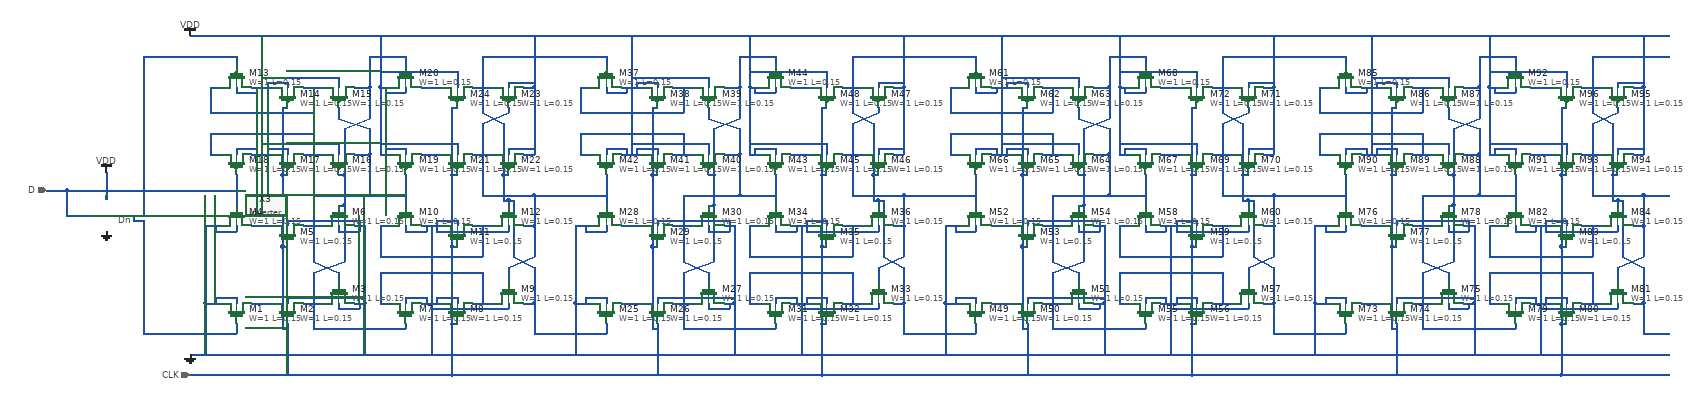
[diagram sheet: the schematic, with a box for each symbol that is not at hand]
v {xschem version=3.4.5 file_version=1.2
}
G {}
K {}
V {}
S {}
E {}
N 525 -420 560 -420 {
lab=Dn}
N 540 -420 540 -410 {
lab=Dn}
N 540 -410 560 -410 {
lab=Dn}
N 410 -420 457.5 -420 {
lab=D}
N 410 -470 410 -420 {
lab=D}
N 370 -470 410 -470 {
lab=D}
N 487.5 -505 487.5 -452.5 {
lab=VDD}
N 740 -500 740 -440 {
lab=D}
N 1070 -500 1070 -440 {
lab=#net1}
N 690 -670 710 -670 {
lab=#net2}
N 690 -540 710 -540 {
lab=#net3}
N 690 -580 690 -540 {
lab=#net3}
N 690 -670 690 -620 {
lab=#net2}
N 680 -400 710 -400 {
lab=GND}
N 680 -400 680 -250 {
lab=GND}
N 680 -250 710 -250 {
lab=GND}
N 1020 -250 1040 -250 {
lab=#net4}
N 1020 -310 1020 -250 {
lab=#net4}
N 1020 -400 1020 -340 {
lab=#net5}
N 1020 -400 1040 -400 {
lab=#net5}
N 970 -250 990 -250 {
lab=GND}
N 990 -400 990 -250 {
lab=GND}
N 970 -400 990 -400 {
lab=GND}
N 1020 -670 1040 -670 {
lab=VDD}
N 1020 -670 1020 -540 {
lab=VDD}
N 1020 -540 1040 -540 {
lab=VDD}
N 1300 -540 1320 -540 {
lab=VDD}
N 1320 -670 1320 -540 {
lab=VDD}
N 1300 -670 1320 -670 {
lab=VDD}
N 970 -670 1000 -670 {
lab=#net6}
N 1000 -730 1000 -670 {
lab=#net6}
N 1000 -730 1070 -730 {
lab=#net6}
N 1070 -730 1070 -710 {
lab=#net6}
N 1000 -670 1000 -610 {
lab=#net6}
N 840 -210 840 -190 {
lab=CLK}
N 970 -540 990 -540 {
lab=#net1}
N 1000 -540 1000 -460 {
lab=#net1}
N 990 -540 1000 -540 {
lab=#net1}
N 1000 -590 1000 -540 {
lab=#net1}
N 940 -610 1000 -590 {
lab=#net1}
N 940 -630 940 -610 {
lab=#net1}
N 1300 -250 1320 -250 {
lab=#net7}
N 1320 -320 1320 -250 {
lab=#net7}
N 1270 -320 1270 -290 {
lab=#net8}
N 1270 -320 1320 -340 {
lab=#net8}
N 1320 -400 1320 -340 {
lab=#net8}
N 1300 -400 1320 -400 {
lab=#net8}
N 1320 -460 1320 -400 {
lab=#net8}
N 1320 -460 1370 -460 {
lab=#net8}
N 740 -730 740 -710 {
lab=Dn}
N 650 -730 740 -730 {
lab=Dn}
N 740 -210 740 -190 {
lab=Dn}
N 650 -190 740 -190 {
lab=Dn}
N 650 -150 1330 -150 {
lab=GND}
N 990 -250 990 -150 {
lab=GND}
N 840 -190 840 -110 {
lab=CLK}
N 650 -770 1330 -770 {
lab=VDD}
N 1020 -770 1020 -670 {
lab=VDD}
N 1320 -770 1320 -670 {
lab=VDD}
N 770 -670 810 -670 {
lab=VDD}
N 770 -540 810 -540 {
lab=VDD}
N 870 -670 910 -670 {
lab=#net2}
N 890 -670 890 -620 {
lab=#net2}
N 690 -620 890 -620 {
lab=#net2}
N 870 -540 910 -540 {
lab=#net3}
N 690 -580 890 -580 {
lab=#net3}
N 890 -580 890 -540 {
lab=#net3}
N 770 -400 810 -400 {
lab=#net9}
N 770 -250 810 -250 {
lab=#net10}
N 870 -250 910 -250 {
lab=#net6}
N 740 -400 740 -390 {
lab=GND}
N 700 -390 740 -390 {
lab=GND}
N 700 -400 700 -390 {
lab=GND}
N 1100 -250 1140 -250 {
lab=GND}
N 1100 -400 1140 -400 {
lab=GND}
N 1200 -250 1240 -250 {
lab=#net4}
N 1200 -400 1240 -400 {
lab=#net5}
N 1020 -340 1220 -340 {
lab=#net5}
N 1220 -400 1220 -340 {
lab=#net5}
N 1070 -260 1070 -250 {
lab=GND}
N 1070 -260 1110 -260 {
lab=GND}
N 1110 -260 1110 -250 {
lab=GND}
N 1020 -310 1220 -310 {
lab=#net4}
N 1220 -310 1220 -250 {
lab=#net4}
N 1100 -540 1140 -540 {
lab=#net11}
N 1200 -540 1240 -540 {
lab=#net8}
N 830 -200 840 -200 {
lab=CLK}
N 830 -360 830 -200 {
lab=CLK}
N 830 -360 840 -360 {
lab=CLK}
N 830 -500 830 -360 {
lab=CLK}
N 830 -500 840 -500 {
lab=CLK}
N 790 -670 790 -540 {
lab=VDD}
N 790 -770 790 -670 {
lab=VDD}
N 940 -500 950 -500 {
lab=#net6}
N 950 -590 950 -500 {
lab=#net6}
N 950 -590 1000 -610 {
lab=#net6}
N 1000 -460 1070 -460 {
lab=#net1}
N 1120 -250 1120 -150 {
lab=GND}
N 1120 -400 1120 -250 {
lab=GND}
N 1160 -210 1170 -210 {
lab=CLK}
N 1160 -360 1170 -360 {
lab=CLK}
N 1160 -500 1170 -500 {
lab=CLK}
N 1200 -670 1240 -670 {
lab=#net7}
N 1160 -630 1160 -500 {
lab=CLK}
N 1160 -630 1170 -630 {
lab=CLK}
N 1100 -670 1140 -670 {
lab=#net12}
N 1220 -730 1370 -730 {
lab=#net7}
N 1220 -730 1220 -670 {
lab=#net7}
N 1260 -500 1270 -500 {
lab=#net7}
N 1260 -600 1260 -500 {
lab=#net7}
N 1220 -620 1260 -600 {
lab=#net7}
N 1220 -670 1220 -620 {
lab=#net7}
N 1270 -630 1270 -620 {
lab=#net8}
N 1220 -600 1270 -620 {
lab=#net8}
N 1220 -600 1220 -540 {
lab=#net8}
N 1220 -540 1220 -460 {
lab=#net8}
N 1220 -460 1320 -460 {
lab=#net8}
N 1270 -450 1270 -440 {
lab=#net7}
N 1270 -450 1280 -450 {
lab=#net7}
N 1280 -450 1280 -340 {
lab=#net7}
N 1280 -340 1320 -320 {
lab=#net7}
N 1260 -450 1270 -450 {
lab=#net7}
N 1260 -500 1260 -450 {
lab=#net7}
N 1320 -250 1320 -190 {
lab=#net7}
N 1320 -190 1330 -190 {
lab=#net7}
N 1160 -210 1160 -110 {
lab=CLK}
N 890 -250 890 -200 {
lab=#net6}
N 890 -200 1070 -200 {
lab=#net6}
N 1070 -210 1070 -200 {
lab=#net6}
N 870 -400 910 -400 {
lab=#net1}
N 890 -460 890 -400 {
lab=#net1}
N 890 -460 1000 -460 {
lab=#net1}
N 940 -440 950 -440 {
lab=#net6}
N 950 -500 950 -440 {
lab=#net6}
N 940 -310 940 -290 {
lab=#net1}
N 890 -330 940 -310 {
lab=#net1}
N 890 -400 890 -330 {
lab=#net1}
N 950 -440 950 -330 {
lab=#net6}
N 890 -310 950 -330 {
lab=#net6}
N 890 -310 890 -250 {
lab=#net6}
N 740 -260 740 -250 {
lab=GND}
N 700 -260 740 -260 {
lab=GND}
N 700 -260 700 -250 {
lab=GND}
N 940 -250 940 -240 {
lab=GND}
N 940 -240 980 -240 {
lab=GND}
N 980 -250 980 -240 {
lab=GND}
N 940 -400 940 -390 {
lab=GND}
N 940 -390 980 -390 {
lab=GND}
N 980 -400 980 -390 {
lab=GND}
N 1070 -400 1070 -390 {
lab=GND}
N 1070 -390 1110 -390 {
lab=GND}
N 1110 -400 1110 -390 {
lab=GND}
N 1170 -410 1170 -400 {
lab=GND}
N 1130 -410 1170 -410 {
lab=GND}
N 1130 -410 1130 -400 {
lab=GND}
N 1170 -260 1170 -250 {
lab=GND}
N 1130 -260 1170 -260 {
lab=GND}
N 1130 -260 1130 -250 {
lab=GND}
N 1160 -500 1160 -360 {
lab=CLK}
N 1160 -360 1160 -210 {
lab=CLK}
N 840 -410 840 -400 {
lab=GND}
N 840 -410 980 -410 {
lab=GND}
N 980 -410 980 -400 {
lab=GND}
N 840 -260 840 -250 {
lab=GND}
N 840 -260 990 -260 {
lab=GND}
N 1270 -400 1270 -390 {
lab=GND}
N 1130 -390 1270 -390 {
lab=GND}
N 1130 -400 1130 -390 {
lab=GND}
N 1270 -250 1270 -240 {
lab=GND}
N 1120 -240 1270 -240 {
lab=GND}
N 840 -680 840 -670 {
lab=VDD}
N 800 -680 840 -680 {
lab=VDD}
N 800 -680 800 -670 {
lab=VDD}
N 740 -670 740 -660 {
lab=VDD}
N 740 -660 780 -660 {
lab=VDD}
N 780 -670 780 -660 {
lab=VDD}
N 740 -550 740 -540 {
lab=VDD}
N 740 -550 780 -550 {
lab=VDD}
N 780 -550 780 -540 {
lab=VDD}
N 840 -550 840 -540 {
lab=VDD}
N 800 -550 840 -550 {
lab=VDD}
N 800 -550 800 -540 {
lab=VDD}
N 940 -690 940 -670 {
lab=VDD}
N 790 -690 940 -690 {
lab=VDD}
N 940 -560 940 -540 {
lab=VDD}
N 790 -560 940 -560 {
lab=VDD}
N 1070 -670 1070 -660 {
lab=VDD}
N 1030 -660 1070 -660 {
lab=VDD}
N 1030 -670 1030 -660 {
lab=VDD}
N 1070 -550 1070 -540 {
lab=VDD}
N 1030 -550 1070 -550 {
lab=VDD}
N 1030 -550 1030 -540 {
lab=VDD}
N 1170 -700 1170 -670 {
lab=VDD}
N 1020 -700 1170 -700 {
lab=VDD}
N 1170 -560 1170 -540 {
lab=VDD}
N 1020 -560 1170 -560 {
lab=VDD}
N 1270 -680 1270 -670 {
lab=VDD}
N 1270 -680 1320 -680 {
lab=VDD}
N 1270 -550 1270 -540 {
lab=VDD}
N 1270 -550 1320 -550 {
lab=VDD}
N 830 -630 830 -500 {
lab=CLK}
N 830 -630 840 -630 {
lab=CLK}
N 680 -250 680 -150 {
lab=GND}
N 410 -470 740 -470 {
lab=D}
N 560 -730 560 -420 {
lab=Dn}
N 560 -730 650 -730 {
lab=Dn}
N 560 -410 560 -190 {
lab=Dn}
N 560 -190 650 -190 {
lab=Dn}
N 650 -110 1160 -110 {
lab=CLK}
N 1460 -500 1460 -440 {
lab=#net13}
N 1790 -500 1790 -440 {
lab=#net14}
N 1410 -670 1430 -670 {
lab=#net15}
N 1410 -540 1430 -540 {
lab=#net16}
N 1410 -580 1410 -540 {
lab=#net16}
N 1410 -670 1410 -620 {
lab=#net15}
N 1400 -400 1430 -400 {
lab=#net17}
N 1400 -400 1400 -250 {
lab=#net17}
N 1400 -250 1430 -250 {
lab=#net17}
N 1740 -250 1760 -250 {
lab=#net18}
N 1740 -310 1740 -250 {
lab=#net18}
N 1740 -400 1740 -340 {
lab=#net19}
N 1740 -400 1760 -400 {
lab=#net19}
N 1690 -250 1710 -250 {
lab=#net17}
N 1710 -400 1710 -250 {
lab=#net17}
N 1690 -400 1710 -400 {
lab=#net17}
N 1740 -670 1760 -670 {
lab=#net20}
N 1740 -670 1740 -540 {
lab=#net20}
N 1740 -540 1760 -540 {
lab=#net20}
N 2020 -540 2040 -540 {
lab=#net20}
N 2040 -670 2040 -540 {
lab=#net20}
N 2020 -670 2040 -670 {
lab=#net20}
N 1690 -670 1720 -670 {
lab=#net21}
N 1720 -730 1720 -670 {
lab=#net21}
N 1720 -730 1790 -730 {
lab=#net21}
N 1790 -730 1790 -710 {
lab=#net21}
N 1720 -670 1720 -610 {
lab=#net21}
N 1560 -210 1560 -190 {
lab=#net22}
N 1690 -540 1710 -540 {
lab=#net14}
N 1720 -540 1720 -460 {
lab=#net14}
N 1710 -540 1720 -540 {
lab=#net14}
N 1720 -590 1720 -540 {
lab=#net14}
N 1660 -610 1720 -590 {
lab=#net14}
N 1660 -630 1660 -610 {
lab=#net14}
N 2020 -250 2040 -250 {
lab=#net23}
N 2040 -320 2040 -250 {
lab=#net23}
N 1990 -320 1990 -290 {
lab=#net24}
N 1990 -320 2040 -340 {
lab=#net24}
N 2040 -400 2040 -340 {
lab=#net24}
N 2020 -400 2040 -400 {
lab=#net24}
N 2040 -460 2040 -400 {
lab=#net24}
N 2040 -460 2090 -460 {
lab=#net24}
N 1460 -730 1460 -710 {
lab=#net25}
N 1460 -210 1460 -190 {
lab=#net26}
N 1370 -150 2050 -150 {
lab=#net17}
N 1710 -250 1710 -150 {
lab=#net17}
N 1560 -190 1560 -110 {
lab=#net22}
N 1370 -770 2050 -770 {
lab=#net20}
N 1740 -770 1740 -670 {
lab=#net20}
N 2040 -770 2040 -670 {
lab=#net20}
N 1490 -670 1530 -670 {
lab=#net20}
N 1490 -540 1530 -540 {
lab=#net20}
N 1590 -670 1630 -670 {
lab=#net15}
N 1610 -670 1610 -620 {
lab=#net15}
N 1410 -620 1610 -620 {
lab=#net15}
N 1590 -540 1630 -540 {
lab=#net16}
N 1410 -580 1610 -580 {
lab=#net16}
N 1610 -580 1610 -540 {
lab=#net16}
N 1490 -400 1530 -400 {
lab=#net27}
N 1490 -250 1530 -250 {
lab=#net28}
N 1590 -250 1630 -250 {
lab=#net21}
N 1460 -400 1460 -390 {
lab=#net17}
N 1420 -390 1460 -390 {
lab=#net17}
N 1420 -400 1420 -390 {
lab=#net17}
N 1820 -250 1860 -250 {
lab=#net17}
N 1820 -400 1860 -400 {
lab=#net17}
N 1920 -250 1960 -250 {
lab=#net18}
N 1920 -400 1960 -400 {
lab=#net19}
N 1740 -340 1940 -340 {
lab=#net19}
N 1940 -400 1940 -340 {
lab=#net19}
N 1790 -260 1790 -250 {
lab=#net17}
N 1790 -260 1830 -260 {
lab=#net17}
N 1830 -260 1830 -250 {
lab=#net17}
N 1740 -310 1940 -310 {
lab=#net18}
N 1940 -310 1940 -250 {
lab=#net18}
N 1820 -540 1860 -540 {
lab=#net29}
N 1920 -540 1960 -540 {
lab=#net24}
N 1550 -200 1560 -200 {
lab=#net22}
N 1550 -360 1550 -200 {
lab=#net22}
N 1550 -360 1560 -360 {
lab=#net22}
N 1550 -500 1550 -360 {
lab=#net22}
N 1550 -500 1560 -500 {
lab=#net22}
N 1510 -670 1510 -540 {
lab=#net20}
N 1510 -770 1510 -670 {
lab=#net20}
N 1660 -500 1670 -500 {
lab=#net21}
N 1670 -590 1670 -500 {
lab=#net21}
N 1670 -590 1720 -610 {
lab=#net21}
N 1720 -460 1790 -460 {
lab=#net14}
N 1840 -250 1840 -150 {
lab=#net17}
N 1840 -400 1840 -250 {
lab=#net17}
N 1880 -210 1890 -210 {
lab=#net22}
N 1880 -360 1890 -360 {
lab=#net22}
N 1880 -500 1890 -500 {
lab=#net22}
N 1920 -670 1960 -670 {
lab=#net23}
N 1880 -630 1880 -500 {
lab=#net22}
N 1880 -630 1890 -630 {
lab=#net22}
N 1820 -670 1860 -670 {
lab=#net30}
N 1940 -730 2090 -730 {
lab=#net23}
N 1940 -730 1940 -670 {
lab=#net23}
N 1980 -500 1990 -500 {
lab=#net23}
N 1980 -600 1980 -500 {
lab=#net23}
N 1940 -620 1980 -600 {
lab=#net23}
N 1940 -670 1940 -620 {
lab=#net23}
N 1990 -630 1990 -620 {
lab=#net24}
N 1940 -600 1990 -620 {
lab=#net24}
N 1940 -600 1940 -540 {
lab=#net24}
N 1940 -540 1940 -460 {
lab=#net24}
N 1940 -460 2040 -460 {
lab=#net24}
N 1990 -450 1990 -440 {
lab=#net23}
N 1990 -450 2000 -450 {
lab=#net23}
N 2000 -450 2000 -340 {
lab=#net23}
N 2000 -340 2040 -320 {
lab=#net23}
N 1980 -450 1990 -450 {
lab=#net23}
N 1980 -500 1980 -450 {
lab=#net23}
N 2040 -250 2040 -190 {
lab=#net23}
N 2040 -190 2050 -190 {
lab=#net23}
N 1880 -210 1880 -110 {
lab=#net22}
N 1610 -250 1610 -200 {
lab=#net21}
N 1610 -200 1790 -200 {
lab=#net21}
N 1790 -210 1790 -200 {
lab=#net21}
N 1590 -400 1630 -400 {
lab=#net14}
N 1610 -460 1610 -400 {
lab=#net14}
N 1610 -460 1720 -460 {
lab=#net14}
N 1660 -440 1670 -440 {
lab=#net21}
N 1670 -500 1670 -440 {
lab=#net21}
N 1660 -310 1660 -290 {
lab=#net14}
N 1610 -330 1660 -310 {
lab=#net14}
N 1610 -400 1610 -330 {
lab=#net14}
N 1670 -440 1670 -330 {
lab=#net21}
N 1610 -310 1670 -330 {
lab=#net21}
N 1610 -310 1610 -250 {
lab=#net21}
N 1460 -260 1460 -250 {
lab=#net17}
N 1420 -260 1460 -260 {
lab=#net17}
N 1420 -260 1420 -250 {
lab=#net17}
N 1660 -250 1660 -240 {
lab=#net17}
N 1660 -240 1700 -240 {
lab=#net17}
N 1700 -250 1700 -240 {
lab=#net17}
N 1660 -400 1660 -390 {
lab=#net17}
N 1660 -390 1700 -390 {
lab=#net17}
N 1700 -400 1700 -390 {
lab=#net17}
N 1790 -400 1790 -390 {
lab=#net17}
N 1790 -390 1830 -390 {
lab=#net17}
N 1830 -400 1830 -390 {
lab=#net17}
N 1890 -410 1890 -400 {
lab=#net17}
N 1850 -410 1890 -410 {
lab=#net17}
N 1850 -410 1850 -400 {
lab=#net17}
N 1890 -260 1890 -250 {
lab=#net17}
N 1850 -260 1890 -260 {
lab=#net17}
N 1850 -260 1850 -250 {
lab=#net17}
N 1880 -500 1880 -360 {
lab=#net22}
N 1880 -360 1880 -210 {
lab=#net22}
N 1560 -410 1560 -400 {
lab=#net17}
N 1560 -410 1700 -410 {
lab=#net17}
N 1700 -410 1700 -400 {
lab=#net17}
N 1560 -260 1560 -250 {
lab=#net17}
N 1560 -260 1710 -260 {
lab=#net17}
N 1990 -400 1990 -390 {
lab=#net17}
N 1850 -390 1990 -390 {
lab=#net17}
N 1850 -400 1850 -390 {
lab=#net17}
N 1990 -250 1990 -240 {
lab=#net17}
N 1840 -240 1990 -240 {
lab=#net17}
N 1560 -680 1560 -670 {
lab=#net20}
N 1520 -680 1560 -680 {
lab=#net20}
N 1520 -680 1520 -670 {
lab=#net20}
N 1460 -670 1460 -660 {
lab=#net20}
N 1460 -660 1500 -660 {
lab=#net20}
N 1500 -670 1500 -660 {
lab=#net20}
N 1460 -550 1460 -540 {
lab=#net20}
N 1460 -550 1500 -550 {
lab=#net20}
N 1500 -550 1500 -540 {
lab=#net20}
N 1560 -550 1560 -540 {
lab=#net20}
N 1520 -550 1560 -550 {
lab=#net20}
N 1520 -550 1520 -540 {
lab=#net20}
N 1660 -690 1660 -670 {
lab=#net20}
N 1510 -690 1660 -690 {
lab=#net20}
N 1660 -560 1660 -540 {
lab=#net20}
N 1510 -560 1660 -560 {
lab=#net20}
N 1790 -670 1790 -660 {
lab=#net20}
N 1750 -660 1790 -660 {
lab=#net20}
N 1750 -670 1750 -660 {
lab=#net20}
N 1790 -550 1790 -540 {
lab=#net20}
N 1750 -550 1790 -550 {
lab=#net20}
N 1750 -550 1750 -540 {
lab=#net20}
N 1890 -700 1890 -670 {
lab=#net20}
N 1740 -700 1890 -700 {
lab=#net20}
N 1890 -560 1890 -540 {
lab=#net20}
N 1740 -560 1890 -560 {
lab=#net20}
N 1990 -680 1990 -670 {
lab=#net20}
N 1990 -680 2040 -680 {
lab=#net20}
N 1990 -550 1990 -540 {
lab=#net20}
N 1990 -550 2040 -550 {
lab=#net20}
N 1550 -630 1550 -500 {
lab=#net22}
N 1550 -630 1560 -630 {
lab=#net22}
N 1400 -250 1400 -150 {
lab=#net17}
N 1370 -110 1880 -110 {
lab=#net22}
N 1160 -110 1330 -110 {
lab=CLK}
N 1370 -190 1460 -190 {
lab=#net26}
N 1370 -730 1460 -730 {
lab=#net25}
N 1370 -460 1460 -460 {
lab=#net13}
N 1330 -770 1370 -770 {
lab=VDD}
N 1330 -190 1370 -190 {
lab=#net7}
N 1330 -150 1370 -150 {
lab=GND}
N 1330 -110 1370 -110 {
lab=CLK}
N 2050 -770 2090 -770 {
lab=#net20}
N 2050 -190 2090 -190 {
lab=#net23}
N 2050 -150 2090 -150 {
lab=#net17}
N 1880 -110 2090 -110 {
lab=#net22}
N 2180 -500 2180 -440 {
lab=#net13}
N 2510 -500 2510 -440 {
lab=#net14}
N 2130 -670 2150 -670 {
lab=#net15}
N 2130 -540 2150 -540 {
lab=#net16}
N 2130 -580 2130 -540 {
lab=#net16}
N 2130 -670 2130 -620 {
lab=#net15}
N 2120 -400 2150 -400 {
lab=#net17}
N 2120 -400 2120 -250 {
lab=#net17}
N 2120 -250 2150 -250 {
lab=#net17}
N 2460 -250 2480 -250 {
lab=#net18}
N 2460 -310 2460 -250 {
lab=#net18}
N 2460 -400 2460 -340 {
lab=#net19}
N 2460 -400 2480 -400 {
lab=#net19}
N 2410 -250 2430 -250 {
lab=#net17}
N 2430 -400 2430 -250 {
lab=#net17}
N 2410 -400 2430 -400 {
lab=#net17}
N 2460 -670 2480 -670 {
lab=#net20}
N 2460 -670 2460 -540 {
lab=#net20}
N 2460 -540 2480 -540 {
lab=#net20}
N 2740 -540 2760 -540 {
lab=#net20}
N 2760 -670 2760 -540 {
lab=#net20}
N 2740 -670 2760 -670 {
lab=#net20}
N 2410 -670 2440 -670 {
lab=#net21}
N 2440 -730 2440 -670 {
lab=#net21}
N 2440 -730 2510 -730 {
lab=#net21}
N 2510 -730 2510 -710 {
lab=#net21}
N 2440 -670 2440 -610 {
lab=#net21}
N 2280 -210 2280 -190 {
lab=#net22}
N 2410 -540 2430 -540 {
lab=#net14}
N 2440 -540 2440 -460 {
lab=#net14}
N 2430 -540 2440 -540 {
lab=#net14}
N 2440 -590 2440 -540 {
lab=#net14}
N 2380 -610 2440 -590 {
lab=#net14}
N 2380 -630 2380 -610 {
lab=#net14}
N 2740 -250 2760 -250 {
lab=#net23}
N 2760 -320 2760 -250 {
lab=#net23}
N 2710 -320 2710 -290 {
lab=#net24}
N 2710 -320 2760 -340 {
lab=#net24}
N 2760 -400 2760 -340 {
lab=#net24}
N 2740 -400 2760 -400 {
lab=#net24}
N 2760 -460 2760 -400 {
lab=#net24}
N 2760 -460 2810 -460 {
lab=#net24}
N 2180 -730 2180 -710 {
lab=#net25}
N 2180 -210 2180 -190 {
lab=#net26}
N 2090 -150 2770 -150 {
lab=#net17}
N 2430 -250 2430 -150 {
lab=#net17}
N 2280 -190 2280 -110 {
lab=#net22}
N 2090 -770 2770 -770 {
lab=#net20}
N 2460 -770 2460 -670 {
lab=#net20}
N 2760 -770 2760 -670 {
lab=#net20}
N 2210 -670 2250 -670 {
lab=#net20}
N 2210 -540 2250 -540 {
lab=#net20}
N 2310 -670 2350 -670 {
lab=#net15}
N 2330 -670 2330 -620 {
lab=#net15}
N 2130 -620 2330 -620 {
lab=#net15}
N 2310 -540 2350 -540 {
lab=#net16}
N 2130 -580 2330 -580 {
lab=#net16}
N 2330 -580 2330 -540 {
lab=#net16}
N 2210 -400 2250 -400 {
lab=#net27}
N 2210 -250 2250 -250 {
lab=#net28}
N 2310 -250 2350 -250 {
lab=#net21}
N 2180 -400 2180 -390 {
lab=#net17}
N 2140 -390 2180 -390 {
lab=#net17}
N 2140 -400 2140 -390 {
lab=#net17}
N 2540 -250 2580 -250 {
lab=#net17}
N 2540 -400 2580 -400 {
lab=#net17}
N 2640 -250 2680 -250 {
lab=#net18}
N 2640 -400 2680 -400 {
lab=#net19}
N 2460 -340 2660 -340 {
lab=#net19}
N 2660 -400 2660 -340 {
lab=#net19}
N 2510 -260 2510 -250 {
lab=#net17}
N 2510 -260 2550 -260 {
lab=#net17}
N 2550 -260 2550 -250 {
lab=#net17}
N 2460 -310 2660 -310 {
lab=#net18}
N 2660 -310 2660 -250 {
lab=#net18}
N 2540 -540 2580 -540 {
lab=#net29}
N 2640 -540 2680 -540 {
lab=#net24}
N 2270 -200 2280 -200 {
lab=#net22}
N 2270 -360 2270 -200 {
lab=#net22}
N 2270 -360 2280 -360 {
lab=#net22}
N 2270 -500 2270 -360 {
lab=#net22}
N 2270 -500 2280 -500 {
lab=#net22}
N 2230 -670 2230 -540 {
lab=#net20}
N 2230 -770 2230 -670 {
lab=#net20}
N 2380 -500 2390 -500 {
lab=#net21}
N 2390 -590 2390 -500 {
lab=#net21}
N 2390 -590 2440 -610 {
lab=#net21}
N 2440 -460 2510 -460 {
lab=#net14}
N 2560 -250 2560 -150 {
lab=#net17}
N 2560 -400 2560 -250 {
lab=#net17}
N 2600 -210 2610 -210 {
lab=#net22}
N 2600 -360 2610 -360 {
lab=#net22}
N 2600 -500 2610 -500 {
lab=#net22}
N 2640 -670 2680 -670 {
lab=#net23}
N 2600 -630 2600 -500 {
lab=#net22}
N 2600 -630 2610 -630 {
lab=#net22}
N 2540 -670 2580 -670 {
lab=#net30}
N 2660 -730 2810 -730 {
lab=#net23}
N 2660 -730 2660 -670 {
lab=#net23}
N 2700 -500 2710 -500 {
lab=#net23}
N 2700 -600 2700 -500 {
lab=#net23}
N 2660 -620 2700 -600 {
lab=#net23}
N 2660 -670 2660 -620 {
lab=#net23}
N 2710 -630 2710 -620 {
lab=#net24}
N 2660 -600 2710 -620 {
lab=#net24}
N 2660 -600 2660 -540 {
lab=#net24}
N 2660 -540 2660 -460 {
lab=#net24}
N 2660 -460 2760 -460 {
lab=#net24}
N 2710 -450 2710 -440 {
lab=#net23}
N 2710 -450 2720 -450 {
lab=#net23}
N 2720 -450 2720 -340 {
lab=#net23}
N 2720 -340 2760 -320 {
lab=#net23}
N 2700 -450 2710 -450 {
lab=#net23}
N 2700 -500 2700 -450 {
lab=#net23}
N 2760 -250 2760 -190 {
lab=#net23}
N 2760 -190 2770 -190 {
lab=#net23}
N 2600 -210 2600 -110 {
lab=#net22}
N 2330 -250 2330 -200 {
lab=#net21}
N 2330 -200 2510 -200 {
lab=#net21}
N 2510 -210 2510 -200 {
lab=#net21}
N 2310 -400 2350 -400 {
lab=#net14}
N 2330 -460 2330 -400 {
lab=#net14}
N 2330 -460 2440 -460 {
lab=#net14}
N 2380 -440 2390 -440 {
lab=#net21}
N 2390 -500 2390 -440 {
lab=#net21}
N 2380 -310 2380 -290 {
lab=#net14}
N 2330 -330 2380 -310 {
lab=#net14}
N 2330 -400 2330 -330 {
lab=#net14}
N 2390 -440 2390 -330 {
lab=#net21}
N 2330 -310 2390 -330 {
lab=#net21}
N 2330 -310 2330 -250 {
lab=#net21}
N 2180 -260 2180 -250 {
lab=#net17}
N 2140 -260 2180 -260 {
lab=#net17}
N 2140 -260 2140 -250 {
lab=#net17}
N 2380 -250 2380 -240 {
lab=#net17}
N 2380 -240 2420 -240 {
lab=#net17}
N 2420 -250 2420 -240 {
lab=#net17}
N 2380 -400 2380 -390 {
lab=#net17}
N 2380 -390 2420 -390 {
lab=#net17}
N 2420 -400 2420 -390 {
lab=#net17}
N 2510 -400 2510 -390 {
lab=#net17}
N 2510 -390 2550 -390 {
lab=#net17}
N 2550 -400 2550 -390 {
lab=#net17}
N 2610 -410 2610 -400 {
lab=#net17}
N 2570 -410 2610 -410 {
lab=#net17}
N 2570 -410 2570 -400 {
lab=#net17}
N 2610 -260 2610 -250 {
lab=#net17}
N 2570 -260 2610 -260 {
lab=#net17}
N 2570 -260 2570 -250 {
lab=#net17}
N 2600 -500 2600 -360 {
lab=#net22}
N 2600 -360 2600 -210 {
lab=#net22}
N 2280 -410 2280 -400 {
lab=#net17}
N 2280 -410 2420 -410 {
lab=#net17}
N 2420 -410 2420 -400 {
lab=#net17}
N 2280 -260 2280 -250 {
lab=#net17}
N 2280 -260 2430 -260 {
lab=#net17}
N 2710 -400 2710 -390 {
lab=#net17}
N 2570 -390 2710 -390 {
lab=#net17}
N 2570 -400 2570 -390 {
lab=#net17}
N 2710 -250 2710 -240 {
lab=#net17}
N 2560 -240 2710 -240 {
lab=#net17}
N 2280 -680 2280 -670 {
lab=#net20}
N 2240 -680 2280 -680 {
lab=#net20}
N 2240 -680 2240 -670 {
lab=#net20}
N 2180 -670 2180 -660 {
lab=#net20}
N 2180 -660 2220 -660 {
lab=#net20}
N 2220 -670 2220 -660 {
lab=#net20}
N 2180 -550 2180 -540 {
lab=#net20}
N 2180 -550 2220 -550 {
lab=#net20}
N 2220 -550 2220 -540 {
lab=#net20}
N 2280 -550 2280 -540 {
lab=#net20}
N 2240 -550 2280 -550 {
lab=#net20}
N 2240 -550 2240 -540 {
lab=#net20}
N 2380 -690 2380 -670 {
lab=#net20}
N 2230 -690 2380 -690 {
lab=#net20}
N 2380 -560 2380 -540 {
lab=#net20}
N 2230 -560 2380 -560 {
lab=#net20}
N 2510 -670 2510 -660 {
lab=#net20}
N 2470 -660 2510 -660 {
lab=#net20}
N 2470 -670 2470 -660 {
lab=#net20}
N 2510 -550 2510 -540 {
lab=#net20}
N 2470 -550 2510 -550 {
lab=#net20}
N 2470 -550 2470 -540 {
lab=#net20}
N 2610 -700 2610 -670 {
lab=#net20}
N 2460 -700 2610 -700 {
lab=#net20}
N 2610 -560 2610 -540 {
lab=#net20}
N 2460 -560 2610 -560 {
lab=#net20}
N 2710 -680 2710 -670 {
lab=#net20}
N 2710 -680 2760 -680 {
lab=#net20}
N 2710 -550 2710 -540 {
lab=#net20}
N 2710 -550 2760 -550 {
lab=#net20}
N 2270 -630 2270 -500 {
lab=#net22}
N 2270 -630 2280 -630 {
lab=#net22}
N 2120 -250 2120 -150 {
lab=#net17}
N 2090 -110 2600 -110 {
lab=#net22}
N 2090 -190 2180 -190 {
lab=#net26}
N 2090 -730 2180 -730 {
lab=#net25}
N 2090 -460 2180 -460 {
lab=#net13}
N 2770 -770 2810 -770 {
lab=#net20}
N 2770 -190 2810 -190 {
lab=#net23}
N 2770 -150 2810 -150 {
lab=#net17}
N 2600 -110 2810 -110 {
lab=#net22}
N 2900 -500 2900 -440 {
lab=#net13}
N 3230 -500 3230 -440 {
lab=#net14}
N 2850 -670 2870 -670 {
lab=#net15}
N 2850 -540 2870 -540 {
lab=#net16}
N 2850 -580 2850 -540 {
lab=#net16}
N 2850 -670 2850 -620 {
lab=#net15}
N 2840 -400 2870 -400 {
lab=#net17}
N 2840 -400 2840 -250 {
lab=#net17}
N 2840 -250 2870 -250 {
lab=#net17}
N 3180 -250 3200 -250 {
lab=#net18}
N 3180 -310 3180 -250 {
lab=#net18}
N 3180 -400 3180 -340 {
lab=#net19}
N 3180 -400 3200 -400 {
lab=#net19}
N 3130 -250 3150 -250 {
lab=#net17}
N 3150 -400 3150 -250 {
lab=#net17}
N 3130 -400 3150 -400 {
lab=#net17}
N 3180 -670 3200 -670 {
lab=#net20}
N 3180 -670 3180 -540 {
lab=#net20}
N 3180 -540 3200 -540 {
lab=#net20}
N 3460 -540 3480 -540 {
lab=#net20}
N 3480 -670 3480 -540 {
lab=#net20}
N 3460 -670 3480 -670 {
lab=#net20}
N 3130 -670 3160 -670 {
lab=#net21}
N 3160 -730 3160 -670 {
lab=#net21}
N 3160 -730 3230 -730 {
lab=#net21}
N 3230 -730 3230 -710 {
lab=#net21}
N 3160 -670 3160 -610 {
lab=#net21}
N 3000 -210 3000 -190 {
lab=#net22}
N 3130 -540 3150 -540 {
lab=#net14}
N 3160 -540 3160 -460 {
lab=#net14}
N 3150 -540 3160 -540 {
lab=#net14}
N 3160 -590 3160 -540 {
lab=#net14}
N 3100 -610 3160 -590 {
lab=#net14}
N 3100 -630 3100 -610 {
lab=#net14}
N 3460 -250 3480 -250 {
lab=#net23}
N 3480 -320 3480 -250 {
lab=#net23}
N 3430 -320 3430 -290 {
lab=#net24}
N 3430 -320 3480 -340 {
lab=#net24}
N 3480 -400 3480 -340 {
lab=#net24}
N 3460 -400 3480 -400 {
lab=#net24}
N 3480 -460 3480 -400 {
lab=#net24}
N 3480 -460 3530 -460 {
lab=#net24}
N 2900 -730 2900 -710 {
lab=#net25}
N 2900 -210 2900 -190 {
lab=#net26}
N 2810 -150 3490 -150 {
lab=#net17}
N 3150 -250 3150 -150 {
lab=#net17}
N 3000 -190 3000 -110 {
lab=#net22}
N 2810 -770 3490 -770 {
lab=#net20}
N 3180 -770 3180 -670 {
lab=#net20}
N 3480 -770 3480 -670 {
lab=#net20}
N 2930 -670 2970 -670 {
lab=#net20}
N 2930 -540 2970 -540 {
lab=#net20}
N 3030 -670 3070 -670 {
lab=#net15}
N 3050 -670 3050 -620 {
lab=#net15}
N 2850 -620 3050 -620 {
lab=#net15}
N 3030 -540 3070 -540 {
lab=#net16}
N 2850 -580 3050 -580 {
lab=#net16}
N 3050 -580 3050 -540 {
lab=#net16}
N 2930 -400 2970 -400 {
lab=#net27}
N 2930 -250 2970 -250 {
lab=#net28}
N 3030 -250 3070 -250 {
lab=#net21}
N 2900 -400 2900 -390 {
lab=#net17}
N 2860 -390 2900 -390 {
lab=#net17}
N 2860 -400 2860 -390 {
lab=#net17}
N 3260 -250 3300 -250 {
lab=#net17}
N 3260 -400 3300 -400 {
lab=#net17}
N 3360 -250 3400 -250 {
lab=#net18}
N 3360 -400 3400 -400 {
lab=#net19}
N 3180 -340 3380 -340 {
lab=#net19}
N 3380 -400 3380 -340 {
lab=#net19}
N 3230 -260 3230 -250 {
lab=#net17}
N 3230 -260 3270 -260 {
lab=#net17}
N 3270 -260 3270 -250 {
lab=#net17}
N 3180 -310 3380 -310 {
lab=#net18}
N 3380 -310 3380 -250 {
lab=#net18}
N 3260 -540 3300 -540 {
lab=#net29}
N 3360 -540 3400 -540 {
lab=#net24}
N 2990 -200 3000 -200 {
lab=#net22}
N 2990 -360 2990 -200 {
lab=#net22}
N 2990 -360 3000 -360 {
lab=#net22}
N 2990 -500 2990 -360 {
lab=#net22}
N 2990 -500 3000 -500 {
lab=#net22}
N 2950 -670 2950 -540 {
lab=#net20}
N 2950 -770 2950 -670 {
lab=#net20}
N 3100 -500 3110 -500 {
lab=#net21}
N 3110 -590 3110 -500 {
lab=#net21}
N 3110 -590 3160 -610 {
lab=#net21}
N 3160 -460 3230 -460 {
lab=#net14}
N 3280 -250 3280 -150 {
lab=#net17}
N 3280 -400 3280 -250 {
lab=#net17}
N 3320 -210 3330 -210 {
lab=#net22}
N 3320 -360 3330 -360 {
lab=#net22}
N 3320 -500 3330 -500 {
lab=#net22}
N 3360 -670 3400 -670 {
lab=#net23}
N 3320 -630 3320 -500 {
lab=#net22}
N 3320 -630 3330 -630 {
lab=#net22}
N 3260 -670 3300 -670 {
lab=#net30}
N 3380 -730 3530 -730 {
lab=#net23}
N 3380 -730 3380 -670 {
lab=#net23}
N 3420 -500 3430 -500 {
lab=#net23}
N 3420 -600 3420 -500 {
lab=#net23}
N 3380 -620 3420 -600 {
lab=#net23}
N 3380 -670 3380 -620 {
lab=#net23}
N 3430 -630 3430 -620 {
lab=#net24}
N 3380 -600 3430 -620 {
lab=#net24}
N 3380 -600 3380 -540 {
lab=#net24}
N 3380 -540 3380 -460 {
lab=#net24}
N 3380 -460 3480 -460 {
lab=#net24}
N 3430 -450 3430 -440 {
lab=#net23}
N 3430 -450 3440 -450 {
lab=#net23}
N 3440 -450 3440 -340 {
lab=#net23}
N 3440 -340 3480 -320 {
lab=#net23}
N 3420 -450 3430 -450 {
lab=#net23}
N 3420 -500 3420 -450 {
lab=#net23}
N 3480 -250 3480 -190 {
lab=#net23}
N 3480 -190 3490 -190 {
lab=#net23}
N 3320 -210 3320 -110 {
lab=#net22}
N 3050 -250 3050 -200 {
lab=#net21}
N 3050 -200 3230 -200 {
lab=#net21}
N 3230 -210 3230 -200 {
lab=#net21}
N 3030 -400 3070 -400 {
lab=#net14}
N 3050 -460 3050 -400 {
lab=#net14}
N 3050 -460 3160 -460 {
lab=#net14}
N 3100 -440 3110 -440 {
lab=#net21}
N 3110 -500 3110 -440 {
lab=#net21}
N 3100 -310 3100 -290 {
lab=#net14}
N 3050 -330 3100 -310 {
lab=#net14}
N 3050 -400 3050 -330 {
lab=#net14}
N 3110 -440 3110 -330 {
lab=#net21}
N 3050 -310 3110 -330 {
lab=#net21}
N 3050 -310 3050 -250 {
lab=#net21}
N 2900 -260 2900 -250 {
lab=#net17}
N 2860 -260 2900 -260 {
lab=#net17}
N 2860 -260 2860 -250 {
lab=#net17}
N 3100 -250 3100 -240 {
lab=#net17}
N 3100 -240 3140 -240 {
lab=#net17}
N 3140 -250 3140 -240 {
lab=#net17}
N 3100 -400 3100 -390 {
lab=#net17}
N 3100 -390 3140 -390 {
lab=#net17}
N 3140 -400 3140 -390 {
lab=#net17}
N 3230 -400 3230 -390 {
lab=#net17}
N 3230 -390 3270 -390 {
lab=#net17}
N 3270 -400 3270 -390 {
lab=#net17}
N 3330 -410 3330 -400 {
lab=#net17}
N 3290 -410 3330 -410 {
lab=#net17}
N 3290 -410 3290 -400 {
lab=#net17}
N 3330 -260 3330 -250 {
lab=#net17}
N 3290 -260 3330 -260 {
lab=#net17}
N 3290 -260 3290 -250 {
lab=#net17}
N 3320 -500 3320 -360 {
lab=#net22}
N 3320 -360 3320 -210 {
lab=#net22}
N 3000 -410 3000 -400 {
lab=#net17}
N 3000 -410 3140 -410 {
lab=#net17}
N 3140 -410 3140 -400 {
lab=#net17}
N 3000 -260 3000 -250 {
lab=#net17}
N 3000 -260 3150 -260 {
lab=#net17}
N 3430 -400 3430 -390 {
lab=#net17}
N 3290 -390 3430 -390 {
lab=#net17}
N 3290 -400 3290 -390 {
lab=#net17}
N 3430 -250 3430 -240 {
lab=#net17}
N 3280 -240 3430 -240 {
lab=#net17}
N 3000 -680 3000 -670 {
lab=#net20}
N 2960 -680 3000 -680 {
lab=#net20}
N 2960 -680 2960 -670 {
lab=#net20}
N 2900 -670 2900 -660 {
lab=#net20}
N 2900 -660 2940 -660 {
lab=#net20}
N 2940 -670 2940 -660 {
lab=#net20}
N 2900 -550 2900 -540 {
lab=#net20}
N 2900 -550 2940 -550 {
lab=#net20}
N 2940 -550 2940 -540 {
lab=#net20}
N 3000 -550 3000 -540 {
lab=#net20}
N 2960 -550 3000 -550 {
lab=#net20}
N 2960 -550 2960 -540 {
lab=#net20}
N 3100 -690 3100 -670 {
lab=#net20}
N 2950 -690 3100 -690 {
lab=#net20}
N 3100 -560 3100 -540 {
lab=#net20}
N 2950 -560 3100 -560 {
lab=#net20}
N 3230 -670 3230 -660 {
lab=#net20}
N 3190 -660 3230 -660 {
lab=#net20}
N 3190 -670 3190 -660 {
lab=#net20}
N 3230 -550 3230 -540 {
lab=#net20}
N 3190 -550 3230 -550 {
lab=#net20}
N 3190 -550 3190 -540 {
lab=#net20}
N 3330 -700 3330 -670 {
lab=#net20}
N 3180 -700 3330 -700 {
lab=#net20}
N 3330 -560 3330 -540 {
lab=#net20}
N 3180 -560 3330 -560 {
lab=#net20}
N 3430 -680 3430 -670 {
lab=#net20}
N 3430 -680 3480 -680 {
lab=#net20}
N 3430 -550 3430 -540 {
lab=#net20}
N 3430 -550 3480 -550 {
lab=#net20}
N 2990 -630 2990 -500 {
lab=#net22}
N 2990 -630 3000 -630 {
lab=#net22}
N 2840 -250 2840 -150 {
lab=#net17}
N 2810 -110 3320 -110 {
lab=#net22}
N 2810 -190 2900 -190 {
lab=#net26}
N 2810 -730 2900 -730 {
lab=#net25}
N 2810 -460 2900 -460 {
lab=#net13}
N 3490 -770 3530 -770 {
lab=#net20}
N 3490 -190 3530 -190 {
lab=#net23}
N 3490 -150 3530 -150 {
lab=#net17}
N 3320 -110 3530 -110 {
lab=#net22}
C {/foss/designs/my_design/projects/inverter_tutorial/xschem_ngspice/inverter.sym} 410 -420 0 0 {name=X3}
C {devices/vdd.sym} 487.5 -505 0 0 {name=l1 lab=VDD}
C {devices/vdd.sym} 650 -770 3 0 {name=l2 lab=VDD}
C {devices/lab_pin.sym} 540 -410 3 0 {name=p5 sig_type=std_logic lab=Dn}
C {devices/gnd.sym} 487.5 -390 0 0 {name=l4 lab=GND}
C {devices/gnd.sym} 650 -150 1 0 {name=l5 lab=GND}
C {sky130_fd_pr/nfet_01v8.sym} 740 -230 1 1 {name=M1
L=0.15
W=1
nf=1 
mult=1
ad="'int((nf+1)/2) * W/nf * 0.29'" 
pd="'2*int((nf+1)/2) * (W/nf + 0.29)'"
as="'int((nf+2)/2) * W/nf * 0.29'" 
ps="'2*int((nf+2)/2) * (W/nf + 0.29)'"
nrd="'0.29 / W'" nrs="'0.29 / W'"
sa=0 sb=0 sd=0
model=nfet_01v8
spiceprefix=X
}
C {sky130_fd_pr/nfet_01v8.sym} 840 -230 1 1 {name=M2
L=0.15
W=1
nf=1 
mult=1
ad="'int((nf+1)/2) * W/nf * 0.29'" 
pd="'2*int((nf+1)/2) * (W/nf + 0.29)'"
as="'int((nf+2)/2) * W/nf * 0.29'" 
ps="'2*int((nf+2)/2) * (W/nf + 0.29)'"
nrd="'0.29 / W'" nrs="'0.29 / W'"
sa=0 sb=0 sd=0
model=nfet_01v8
spiceprefix=X
}
C {sky130_fd_pr/nfet_01v8.sym} 940 -270 1 0 {name=M3
L=0.15
W=1
nf=1 
mult=1
ad="'int((nf+1)/2) * W/nf * 0.29'" 
pd="'2*int((nf+1)/2) * (W/nf + 0.29)'"
as="'int((nf+2)/2) * W/nf * 0.29'" 
ps="'2*int((nf+2)/2) * (W/nf + 0.29)'"
nrd="'0.29 / W'" nrs="'0.29 / W'"
sa=0 sb=0 sd=0
model=nfet_01v8
spiceprefix=X
}
C {sky130_fd_pr/nfet_01v8.sym} 740 -420 1 0 {name=M4
L=0.15
W=1
nf=1 
mult=1
ad="'int((nf+1)/2) * W/nf * 0.29'" 
pd="'2*int((nf+1)/2) * (W/nf + 0.29)'"
as="'int((nf+2)/2) * W/nf * 0.29'" 
ps="'2*int((nf+2)/2) * (W/nf + 0.29)'"
nrd="'0.29 / W'" nrs="'0.29 / W'"
sa=0 sb=0 sd=0
model=nfet_01v8
spiceprefix=X
}
C {sky130_fd_pr/nfet_01v8.sym} 840 -380 3 0 {name=M5
L=0.15
W=1
nf=1 
mult=1
ad="'int((nf+1)/2) * W/nf * 0.29'" 
pd="'2*int((nf+1)/2) * (W/nf + 0.29)'"
as="'int((nf+2)/2) * W/nf * 0.29'" 
ps="'2*int((nf+2)/2) * (W/nf + 0.29)'"
nrd="'0.29 / W'" nrs="'0.29 / W'"
sa=0 sb=0 sd=0
model=nfet_01v8
spiceprefix=X
}
C {sky130_fd_pr/nfet_01v8.sym} 940 -420 3 1 {name=M6
L=0.15
W=1
nf=1 
mult=1
ad="'int((nf+1)/2) * W/nf * 0.29'" 
pd="'2*int((nf+1)/2) * (W/nf + 0.29)'"
as="'int((nf+2)/2) * W/nf * 0.29'" 
ps="'2*int((nf+2)/2) * (W/nf + 0.29)'"
nrd="'0.29 / W'" nrs="'0.29 / W'"
sa=0 sb=0 sd=0
model=nfet_01v8
spiceprefix=X
}
C {sky130_fd_pr/nfet_01v8.sym} 1070 -230 3 0 {name=M7
L=0.15
W=1
nf=1 
mult=1
ad="'int((nf+1)/2) * W/nf * 0.29'" 
pd="'2*int((nf+1)/2) * (W/nf + 0.29)'"
as="'int((nf+2)/2) * W/nf * 0.29'" 
ps="'2*int((nf+2)/2) * (W/nf + 0.29)'"
nrd="'0.29 / W'" nrs="'0.29 / W'"
sa=0 sb=0 sd=0
model=nfet_01v8
spiceprefix=X
}
C {sky130_fd_pr/nfet_01v8.sym} 1170 -230 1 1 {name=M8
L=0.15
W=1
nf=1 
mult=1
ad="'int((nf+1)/2) * W/nf * 0.29'" 
pd="'2*int((nf+1)/2) * (W/nf + 0.29)'"
as="'int((nf+2)/2) * W/nf * 0.29'" 
ps="'2*int((nf+2)/2) * (W/nf + 0.29)'"
nrd="'0.29 / W'" nrs="'0.29 / W'"
sa=0 sb=0 sd=0
model=nfet_01v8
spiceprefix=X
}
C {sky130_fd_pr/nfet_01v8.sym} 1270 -270 1 0 {name=M9
L=0.15
W=1
nf=1 
mult=1
ad="'int((nf+1)/2) * W/nf * 0.29'" 
pd="'2*int((nf+1)/2) * (W/nf + 0.29)'"
as="'int((nf+2)/2) * W/nf * 0.29'" 
ps="'2*int((nf+2)/2) * (W/nf + 0.29)'"
nrd="'0.29 / W'" nrs="'0.29 / W'"
sa=0 sb=0 sd=0
model=nfet_01v8
spiceprefix=X
}
C {sky130_fd_pr/nfet_01v8.sym} 1070 -420 3 1 {name=M10
L=0.15
W=1
nf=1 
mult=1
ad="'int((nf+1)/2) * W/nf * 0.29'" 
pd="'2*int((nf+1)/2) * (W/nf + 0.29)'"
as="'int((nf+2)/2) * W/nf * 0.29'" 
ps="'2*int((nf+2)/2) * (W/nf + 0.29)'"
nrd="'0.29 / W'" nrs="'0.29 / W'"
sa=0 sb=0 sd=0
model=nfet_01v8
spiceprefix=X
}
C {sky130_fd_pr/nfet_01v8.sym} 1170 -380 1 1 {name=M11
L=0.15
W=1
nf=1 
mult=1
ad="'int((nf+1)/2) * W/nf * 0.29'" 
pd="'2*int((nf+1)/2) * (W/nf + 0.29)'"
as="'int((nf+2)/2) * W/nf * 0.29'" 
ps="'2*int((nf+2)/2) * (W/nf + 0.29)'"
nrd="'0.29 / W'" nrs="'0.29 / W'"
sa=0 sb=0 sd=0
model=nfet_01v8
spiceprefix=X
}
C {sky130_fd_pr/nfet_01v8.sym} 1270 -420 1 0 {name=M12
L=0.15
W=1
nf=1 
mult=1
ad="'int((nf+1)/2) * W/nf * 0.29'" 
pd="'2*int((nf+1)/2) * (W/nf + 0.29)'"
as="'int((nf+2)/2) * W/nf * 0.29'" 
ps="'2*int((nf+2)/2) * (W/nf + 0.29)'"
nrd="'0.29 / W'" nrs="'0.29 / W'"
sa=0 sb=0 sd=0
model=nfet_01v8
spiceprefix=X
}
C {sky130_fd_pr/pfet_01v8.sym} 740 -690 1 0 {name=M13
L=0.15
W=1
nf=1
mult=1
ad="'int((nf+1)/2) * W/nf * 0.29'" 
pd="'2*int((nf+1)/2) * (W/nf + 0.29)'"
as="'int((nf+2)/2) * W/nf * 0.29'" 
ps="'2*int((nf+2)/2) * (W/nf + 0.29)'"
nrd="'0.29 / W'" nrs="'0.29 / W'"
sa=0 sb=0 sd=0
model=pfet_01v8
spiceprefix=X
}
C {sky130_fd_pr/pfet_01v8.sym} 840 -650 3 0 {name=M14
L=0.15
W=1
nf=1
mult=1
ad="'int((nf+1)/2) * W/nf * 0.29'" 
pd="'2*int((nf+1)/2) * (W/nf + 0.29)'"
as="'int((nf+2)/2) * W/nf * 0.29'" 
ps="'2*int((nf+2)/2) * (W/nf + 0.29)'"
nrd="'0.29 / W'" nrs="'0.29 / W'"
sa=0 sb=0 sd=0
model=pfet_01v8
spiceprefix=X
}
C {sky130_fd_pr/pfet_01v8.sym} 940 -650 3 0 {name=M15
L=0.15
W=1
nf=1
mult=1
ad="'int((nf+1)/2) * W/nf * 0.29'" 
pd="'2*int((nf+1)/2) * (W/nf + 0.29)'"
as="'int((nf+2)/2) * W/nf * 0.29'" 
ps="'2*int((nf+2)/2) * (W/nf + 0.29)'"
nrd="'0.29 / W'" nrs="'0.29 / W'"
sa=0 sb=0 sd=0
model=pfet_01v8
spiceprefix=X
}
C {sky130_fd_pr/pfet_01v8.sym} 940 -520 3 0 {name=M16
L=0.15
W=1
nf=1
mult=1
ad="'int((nf+1)/2) * W/nf * 0.29'" 
pd="'2*int((nf+1)/2) * (W/nf + 0.29)'"
as="'int((nf+2)/2) * W/nf * 0.29'" 
ps="'2*int((nf+2)/2) * (W/nf + 0.29)'"
nrd="'0.29 / W'" nrs="'0.29 / W'"
sa=0 sb=0 sd=0
model=pfet_01v8
spiceprefix=X
}
C {sky130_fd_pr/pfet_01v8.sym} 840 -520 3 0 {name=M17
L=0.15
W=1
nf=1
mult=1
ad="'int((nf+1)/2) * W/nf * 0.29'" 
pd="'2*int((nf+1)/2) * (W/nf + 0.29)'"
as="'int((nf+2)/2) * W/nf * 0.29'" 
ps="'2*int((nf+2)/2) * (W/nf + 0.29)'"
nrd="'0.29 / W'" nrs="'0.29 / W'"
sa=0 sb=0 sd=0
model=pfet_01v8
spiceprefix=X
}
C {sky130_fd_pr/pfet_01v8.sym} 740 -520 1 1 {name=M18
L=0.15
W=1
nf=1
mult=1
ad="'int((nf+1)/2) * W/nf * 0.29'" 
pd="'2*int((nf+1)/2) * (W/nf + 0.29)'"
as="'int((nf+2)/2) * W/nf * 0.29'" 
ps="'2*int((nf+2)/2) * (W/nf + 0.29)'"
nrd="'0.29 / W'" nrs="'0.29 / W'"
sa=0 sb=0 sd=0
model=pfet_01v8
spiceprefix=X
}
C {sky130_fd_pr/pfet_01v8.sym} 1070 -520 3 0 {name=M19
L=0.15
W=1
nf=1
mult=1
ad="'int((nf+1)/2) * W/nf * 0.29'" 
pd="'2*int((nf+1)/2) * (W/nf + 0.29)'"
as="'int((nf+2)/2) * W/nf * 0.29'" 
ps="'2*int((nf+2)/2) * (W/nf + 0.29)'"
nrd="'0.29 / W'" nrs="'0.29 / W'"
sa=0 sb=0 sd=0
model=pfet_01v8
spiceprefix=X
}
C {sky130_fd_pr/pfet_01v8.sym} 1070 -690 3 1 {name=M20
L=0.15
W=1
nf=1
mult=1
ad="'int((nf+1)/2) * W/nf * 0.29'" 
pd="'2*int((nf+1)/2) * (W/nf + 0.29)'"
as="'int((nf+2)/2) * W/nf * 0.29'" 
ps="'2*int((nf+2)/2) * (W/nf + 0.29)'"
nrd="'0.29 / W'" nrs="'0.29 / W'"
sa=0 sb=0 sd=0
model=pfet_01v8
spiceprefix=X
}
C {sky130_fd_pr/pfet_01v8.sym} 1170 -520 3 0 {name=M21
L=0.15
W=1
nf=1
mult=1
ad="'int((nf+1)/2) * W/nf * 0.29'" 
pd="'2*int((nf+1)/2) * (W/nf + 0.29)'"
as="'int((nf+2)/2) * W/nf * 0.29'" 
ps="'2*int((nf+2)/2) * (W/nf + 0.29)'"
nrd="'0.29 / W'" nrs="'0.29 / W'"
sa=0 sb=0 sd=0
model=pfet_01v8
spiceprefix=X
}
C {sky130_fd_pr/pfet_01v8.sym} 1270 -520 1 1 {name=M22
L=0.15
W=1
nf=1
mult=1
ad="'int((nf+1)/2) * W/nf * 0.29'" 
pd="'2*int((nf+1)/2) * (W/nf + 0.29)'"
as="'int((nf+2)/2) * W/nf * 0.29'" 
ps="'2*int((nf+2)/2) * (W/nf + 0.29)'"
nrd="'0.29 / W'" nrs="'0.29 / W'"
sa=0 sb=0 sd=0
model=pfet_01v8
spiceprefix=X
}
C {sky130_fd_pr/pfet_01v8.sym} 1270 -650 1 1 {name=M23
L=0.15
W=1
nf=1
mult=1
ad="'int((nf+1)/2) * W/nf * 0.29'" 
pd="'2*int((nf+1)/2) * (W/nf + 0.29)'"
as="'int((nf+2)/2) * W/nf * 0.29'" 
ps="'2*int((nf+2)/2) * (W/nf + 0.29)'"
nrd="'0.29 / W'" nrs="'0.29 / W'"
sa=0 sb=0 sd=0
model=pfet_01v8
spiceprefix=X
}
C {sky130_fd_pr/pfet_01v8.sym} 1170 -650 3 0 {name=M24
L=0.15
W=1
nf=1
mult=1
ad="'int((nf+1)/2) * W/nf * 0.29'" 
pd="'2*int((nf+1)/2) * (W/nf + 0.29)'"
as="'int((nf+2)/2) * W/nf * 0.29'" 
ps="'2*int((nf+2)/2) * (W/nf + 0.29)'"
nrd="'0.29 / W'" nrs="'0.29 / W'"
sa=0 sb=0 sd=0
model=pfet_01v8
spiceprefix=X
}
C {devices/ipin.sym} 370 -470 0 0 {name=p6 lab=D}
C {devices/ipin.sym} 650 -110 0 0 {name=p1 lab=CLK}
C {sky130_fd_pr/nfet_01v8.sym} 1460 -230 1 1 {name=M25
L=0.15
W=1
nf=1 
mult=1
ad="'int((nf+1)/2) * W/nf * 0.29'" 
pd="'2*int((nf+1)/2) * (W/nf + 0.29)'"
as="'int((nf+2)/2) * W/nf * 0.29'" 
ps="'2*int((nf+2)/2) * (W/nf + 0.29)'"
nrd="'0.29 / W'" nrs="'0.29 / W'"
sa=0 sb=0 sd=0
model=nfet_01v8
spiceprefix=X
}
C {sky130_fd_pr/nfet_01v8.sym} 1560 -230 1 1 {name=M26
L=0.15
W=1
nf=1 
mult=1
ad="'int((nf+1)/2) * W/nf * 0.29'" 
pd="'2*int((nf+1)/2) * (W/nf + 0.29)'"
as="'int((nf+2)/2) * W/nf * 0.29'" 
ps="'2*int((nf+2)/2) * (W/nf + 0.29)'"
nrd="'0.29 / W'" nrs="'0.29 / W'"
sa=0 sb=0 sd=0
model=nfet_01v8
spiceprefix=X
}
C {sky130_fd_pr/nfet_01v8.sym} 1660 -270 1 0 {name=M27
L=0.15
W=1
nf=1 
mult=1
ad="'int((nf+1)/2) * W/nf * 0.29'" 
pd="'2*int((nf+1)/2) * (W/nf + 0.29)'"
as="'int((nf+2)/2) * W/nf * 0.29'" 
ps="'2*int((nf+2)/2) * (W/nf + 0.29)'"
nrd="'0.29 / W'" nrs="'0.29 / W'"
sa=0 sb=0 sd=0
model=nfet_01v8
spiceprefix=X
}
C {sky130_fd_pr/nfet_01v8.sym} 1460 -420 1 0 {name=M28
L=0.15
W=1
nf=1 
mult=1
ad="'int((nf+1)/2) * W/nf * 0.29'" 
pd="'2*int((nf+1)/2) * (W/nf + 0.29)'"
as="'int((nf+2)/2) * W/nf * 0.29'" 
ps="'2*int((nf+2)/2) * (W/nf + 0.29)'"
nrd="'0.29 / W'" nrs="'0.29 / W'"
sa=0 sb=0 sd=0
model=nfet_01v8
spiceprefix=X
}
C {sky130_fd_pr/nfet_01v8.sym} 1560 -380 3 0 {name=M29
L=0.15
W=1
nf=1 
mult=1
ad="'int((nf+1)/2) * W/nf * 0.29'" 
pd="'2*int((nf+1)/2) * (W/nf + 0.29)'"
as="'int((nf+2)/2) * W/nf * 0.29'" 
ps="'2*int((nf+2)/2) * (W/nf + 0.29)'"
nrd="'0.29 / W'" nrs="'0.29 / W'"
sa=0 sb=0 sd=0
model=nfet_01v8
spiceprefix=X
}
C {sky130_fd_pr/nfet_01v8.sym} 1660 -420 3 1 {name=M30
L=0.15
W=1
nf=1 
mult=1
ad="'int((nf+1)/2) * W/nf * 0.29'" 
pd="'2*int((nf+1)/2) * (W/nf + 0.29)'"
as="'int((nf+2)/2) * W/nf * 0.29'" 
ps="'2*int((nf+2)/2) * (W/nf + 0.29)'"
nrd="'0.29 / W'" nrs="'0.29 / W'"
sa=0 sb=0 sd=0
model=nfet_01v8
spiceprefix=X
}
C {sky130_fd_pr/nfet_01v8.sym} 1790 -230 3 0 {name=M31
L=0.15
W=1
nf=1 
mult=1
ad="'int((nf+1)/2) * W/nf * 0.29'" 
pd="'2*int((nf+1)/2) * (W/nf + 0.29)'"
as="'int((nf+2)/2) * W/nf * 0.29'" 
ps="'2*int((nf+2)/2) * (W/nf + 0.29)'"
nrd="'0.29 / W'" nrs="'0.29 / W'"
sa=0 sb=0 sd=0
model=nfet_01v8
spiceprefix=X
}
C {sky130_fd_pr/nfet_01v8.sym} 1890 -230 1 1 {name=M32
L=0.15
W=1
nf=1 
mult=1
ad="'int((nf+1)/2) * W/nf * 0.29'" 
pd="'2*int((nf+1)/2) * (W/nf + 0.29)'"
as="'int((nf+2)/2) * W/nf * 0.29'" 
ps="'2*int((nf+2)/2) * (W/nf + 0.29)'"
nrd="'0.29 / W'" nrs="'0.29 / W'"
sa=0 sb=0 sd=0
model=nfet_01v8
spiceprefix=X
}
C {sky130_fd_pr/nfet_01v8.sym} 1990 -270 1 0 {name=M33
L=0.15
W=1
nf=1 
mult=1
ad="'int((nf+1)/2) * W/nf * 0.29'" 
pd="'2*int((nf+1)/2) * (W/nf + 0.29)'"
as="'int((nf+2)/2) * W/nf * 0.29'" 
ps="'2*int((nf+2)/2) * (W/nf + 0.29)'"
nrd="'0.29 / W'" nrs="'0.29 / W'"
sa=0 sb=0 sd=0
model=nfet_01v8
spiceprefix=X
}
C {sky130_fd_pr/nfet_01v8.sym} 1790 -420 3 1 {name=M34
L=0.15
W=1
nf=1 
mult=1
ad="'int((nf+1)/2) * W/nf * 0.29'" 
pd="'2*int((nf+1)/2) * (W/nf + 0.29)'"
as="'int((nf+2)/2) * W/nf * 0.29'" 
ps="'2*int((nf+2)/2) * (W/nf + 0.29)'"
nrd="'0.29 / W'" nrs="'0.29 / W'"
sa=0 sb=0 sd=0
model=nfet_01v8
spiceprefix=X
}
C {sky130_fd_pr/nfet_01v8.sym} 1890 -380 1 1 {name=M35
L=0.15
W=1
nf=1 
mult=1
ad="'int((nf+1)/2) * W/nf * 0.29'" 
pd="'2*int((nf+1)/2) * (W/nf + 0.29)'"
as="'int((nf+2)/2) * W/nf * 0.29'" 
ps="'2*int((nf+2)/2) * (W/nf + 0.29)'"
nrd="'0.29 / W'" nrs="'0.29 / W'"
sa=0 sb=0 sd=0
model=nfet_01v8
spiceprefix=X
}
C {sky130_fd_pr/nfet_01v8.sym} 1990 -420 1 0 {name=M36
L=0.15
W=1
nf=1 
mult=1
ad="'int((nf+1)/2) * W/nf * 0.29'" 
pd="'2*int((nf+1)/2) * (W/nf + 0.29)'"
as="'int((nf+2)/2) * W/nf * 0.29'" 
ps="'2*int((nf+2)/2) * (W/nf + 0.29)'"
nrd="'0.29 / W'" nrs="'0.29 / W'"
sa=0 sb=0 sd=0
model=nfet_01v8
spiceprefix=X
}
C {sky130_fd_pr/pfet_01v8.sym} 1460 -690 1 0 {name=M37
L=0.15
W=1
nf=1
mult=1
ad="'int((nf+1)/2) * W/nf * 0.29'" 
pd="'2*int((nf+1)/2) * (W/nf + 0.29)'"
as="'int((nf+2)/2) * W/nf * 0.29'" 
ps="'2*int((nf+2)/2) * (W/nf + 0.29)'"
nrd="'0.29 / W'" nrs="'0.29 / W'"
sa=0 sb=0 sd=0
model=pfet_01v8
spiceprefix=X
}
C {sky130_fd_pr/pfet_01v8.sym} 1560 -650 3 0 {name=M38
L=0.15
W=1
nf=1
mult=1
ad="'int((nf+1)/2) * W/nf * 0.29'" 
pd="'2*int((nf+1)/2) * (W/nf + 0.29)'"
as="'int((nf+2)/2) * W/nf * 0.29'" 
ps="'2*int((nf+2)/2) * (W/nf + 0.29)'"
nrd="'0.29 / W'" nrs="'0.29 / W'"
sa=0 sb=0 sd=0
model=pfet_01v8
spiceprefix=X
}
C {sky130_fd_pr/pfet_01v8.sym} 1660 -650 3 0 {name=M39
L=0.15
W=1
nf=1
mult=1
ad="'int((nf+1)/2) * W/nf * 0.29'" 
pd="'2*int((nf+1)/2) * (W/nf + 0.29)'"
as="'int((nf+2)/2) * W/nf * 0.29'" 
ps="'2*int((nf+2)/2) * (W/nf + 0.29)'"
nrd="'0.29 / W'" nrs="'0.29 / W'"
sa=0 sb=0 sd=0
model=pfet_01v8
spiceprefix=X
}
C {sky130_fd_pr/pfet_01v8.sym} 1660 -520 3 0 {name=M40
L=0.15
W=1
nf=1
mult=1
ad="'int((nf+1)/2) * W/nf * 0.29'" 
pd="'2*int((nf+1)/2) * (W/nf + 0.29)'"
as="'int((nf+2)/2) * W/nf * 0.29'" 
ps="'2*int((nf+2)/2) * (W/nf + 0.29)'"
nrd="'0.29 / W'" nrs="'0.29 / W'"
sa=0 sb=0 sd=0
model=pfet_01v8
spiceprefix=X
}
C {sky130_fd_pr/pfet_01v8.sym} 1560 -520 3 0 {name=M41
L=0.15
W=1
nf=1
mult=1
ad="'int((nf+1)/2) * W/nf * 0.29'" 
pd="'2*int((nf+1)/2) * (W/nf + 0.29)'"
as="'int((nf+2)/2) * W/nf * 0.29'" 
ps="'2*int((nf+2)/2) * (W/nf + 0.29)'"
nrd="'0.29 / W'" nrs="'0.29 / W'"
sa=0 sb=0 sd=0
model=pfet_01v8
spiceprefix=X
}
C {sky130_fd_pr/pfet_01v8.sym} 1460 -520 1 1 {name=M42
L=0.15
W=1
nf=1
mult=1
ad="'int((nf+1)/2) * W/nf * 0.29'" 
pd="'2*int((nf+1)/2) * (W/nf + 0.29)'"
as="'int((nf+2)/2) * W/nf * 0.29'" 
ps="'2*int((nf+2)/2) * (W/nf + 0.29)'"
nrd="'0.29 / W'" nrs="'0.29 / W'"
sa=0 sb=0 sd=0
model=pfet_01v8
spiceprefix=X
}
C {sky130_fd_pr/pfet_01v8.sym} 1790 -520 3 0 {name=M43
L=0.15
W=1
nf=1
mult=1
ad="'int((nf+1)/2) * W/nf * 0.29'" 
pd="'2*int((nf+1)/2) * (W/nf + 0.29)'"
as="'int((nf+2)/2) * W/nf * 0.29'" 
ps="'2*int((nf+2)/2) * (W/nf + 0.29)'"
nrd="'0.29 / W'" nrs="'0.29 / W'"
sa=0 sb=0 sd=0
model=pfet_01v8
spiceprefix=X
}
C {sky130_fd_pr/pfet_01v8.sym} 1790 -690 3 1 {name=M44
L=0.15
W=1
nf=1
mult=1
ad="'int((nf+1)/2) * W/nf * 0.29'" 
pd="'2*int((nf+1)/2) * (W/nf + 0.29)'"
as="'int((nf+2)/2) * W/nf * 0.29'" 
ps="'2*int((nf+2)/2) * (W/nf + 0.29)'"
nrd="'0.29 / W'" nrs="'0.29 / W'"
sa=0 sb=0 sd=0
model=pfet_01v8
spiceprefix=X
}
C {sky130_fd_pr/pfet_01v8.sym} 1890 -520 3 0 {name=M45
L=0.15
W=1
nf=1
mult=1
ad="'int((nf+1)/2) * W/nf * 0.29'" 
pd="'2*int((nf+1)/2) * (W/nf + 0.29)'"
as="'int((nf+2)/2) * W/nf * 0.29'" 
ps="'2*int((nf+2)/2) * (W/nf + 0.29)'"
nrd="'0.29 / W'" nrs="'0.29 / W'"
sa=0 sb=0 sd=0
model=pfet_01v8
spiceprefix=X
}
C {sky130_fd_pr/pfet_01v8.sym} 1990 -520 1 1 {name=M46
L=0.15
W=1
nf=1
mult=1
ad="'int((nf+1)/2) * W/nf * 0.29'" 
pd="'2*int((nf+1)/2) * (W/nf + 0.29)'"
as="'int((nf+2)/2) * W/nf * 0.29'" 
ps="'2*int((nf+2)/2) * (W/nf + 0.29)'"
nrd="'0.29 / W'" nrs="'0.29 / W'"
sa=0 sb=0 sd=0
model=pfet_01v8
spiceprefix=X
}
C {sky130_fd_pr/pfet_01v8.sym} 1990 -650 1 1 {name=M47
L=0.15
W=1
nf=1
mult=1
ad="'int((nf+1)/2) * W/nf * 0.29'" 
pd="'2*int((nf+1)/2) * (W/nf + 0.29)'"
as="'int((nf+2)/2) * W/nf * 0.29'" 
ps="'2*int((nf+2)/2) * (W/nf + 0.29)'"
nrd="'0.29 / W'" nrs="'0.29 / W'"
sa=0 sb=0 sd=0
model=pfet_01v8
spiceprefix=X
}
C {sky130_fd_pr/pfet_01v8.sym} 1890 -650 3 0 {name=M48
L=0.15
W=1
nf=1
mult=1
ad="'int((nf+1)/2) * W/nf * 0.29'" 
pd="'2*int((nf+1)/2) * (W/nf + 0.29)'"
as="'int((nf+2)/2) * W/nf * 0.29'" 
ps="'2*int((nf+2)/2) * (W/nf + 0.29)'"
nrd="'0.29 / W'" nrs="'0.29 / W'"
sa=0 sb=0 sd=0
model=pfet_01v8
spiceprefix=X
}
C {sky130_fd_pr/nfet_01v8.sym} 2180 -230 1 1 {name=M49
L=0.15
W=1
nf=1 
mult=1
ad="'int((nf+1)/2) * W/nf * 0.29'" 
pd="'2*int((nf+1)/2) * (W/nf + 0.29)'"
as="'int((nf+2)/2) * W/nf * 0.29'" 
ps="'2*int((nf+2)/2) * (W/nf + 0.29)'"
nrd="'0.29 / W'" nrs="'0.29 / W'"
sa=0 sb=0 sd=0
model=nfet_01v8
spiceprefix=X
}
C {sky130_fd_pr/nfet_01v8.sym} 2280 -230 1 1 {name=M50
L=0.15
W=1
nf=1 
mult=1
ad="'int((nf+1)/2) * W/nf * 0.29'" 
pd="'2*int((nf+1)/2) * (W/nf + 0.29)'"
as="'int((nf+2)/2) * W/nf * 0.29'" 
ps="'2*int((nf+2)/2) * (W/nf + 0.29)'"
nrd="'0.29 / W'" nrs="'0.29 / W'"
sa=0 sb=0 sd=0
model=nfet_01v8
spiceprefix=X
}
C {sky130_fd_pr/nfet_01v8.sym} 2380 -270 1 0 {name=M51
L=0.15
W=1
nf=1 
mult=1
ad="'int((nf+1)/2) * W/nf * 0.29'" 
pd="'2*int((nf+1)/2) * (W/nf + 0.29)'"
as="'int((nf+2)/2) * W/nf * 0.29'" 
ps="'2*int((nf+2)/2) * (W/nf + 0.29)'"
nrd="'0.29 / W'" nrs="'0.29 / W'"
sa=0 sb=0 sd=0
model=nfet_01v8
spiceprefix=X
}
C {sky130_fd_pr/nfet_01v8.sym} 2180 -420 1 0 {name=M52
L=0.15
W=1
nf=1 
mult=1
ad="'int((nf+1)/2) * W/nf * 0.29'" 
pd="'2*int((nf+1)/2) * (W/nf + 0.29)'"
as="'int((nf+2)/2) * W/nf * 0.29'" 
ps="'2*int((nf+2)/2) * (W/nf + 0.29)'"
nrd="'0.29 / W'" nrs="'0.29 / W'"
sa=0 sb=0 sd=0
model=nfet_01v8
spiceprefix=X
}
C {sky130_fd_pr/nfet_01v8.sym} 2280 -380 3 0 {name=M53
L=0.15
W=1
nf=1 
mult=1
ad="'int((nf+1)/2) * W/nf * 0.29'" 
pd="'2*int((nf+1)/2) * (W/nf + 0.29)'"
as="'int((nf+2)/2) * W/nf * 0.29'" 
ps="'2*int((nf+2)/2) * (W/nf + 0.29)'"
nrd="'0.29 / W'" nrs="'0.29 / W'"
sa=0 sb=0 sd=0
model=nfet_01v8
spiceprefix=X
}
C {sky130_fd_pr/nfet_01v8.sym} 2380 -420 3 1 {name=M54
L=0.15
W=1
nf=1 
mult=1
ad="'int((nf+1)/2) * W/nf * 0.29'" 
pd="'2*int((nf+1)/2) * (W/nf + 0.29)'"
as="'int((nf+2)/2) * W/nf * 0.29'" 
ps="'2*int((nf+2)/2) * (W/nf + 0.29)'"
nrd="'0.29 / W'" nrs="'0.29 / W'"
sa=0 sb=0 sd=0
model=nfet_01v8
spiceprefix=X
}
C {sky130_fd_pr/nfet_01v8.sym} 2510 -230 3 0 {name=M55
L=0.15
W=1
nf=1 
mult=1
ad="'int((nf+1)/2) * W/nf * 0.29'" 
pd="'2*int((nf+1)/2) * (W/nf + 0.29)'"
as="'int((nf+2)/2) * W/nf * 0.29'" 
ps="'2*int((nf+2)/2) * (W/nf + 0.29)'"
nrd="'0.29 / W'" nrs="'0.29 / W'"
sa=0 sb=0 sd=0
model=nfet_01v8
spiceprefix=X
}
C {sky130_fd_pr/nfet_01v8.sym} 2610 -230 1 1 {name=M56
L=0.15
W=1
nf=1 
mult=1
ad="'int((nf+1)/2) * W/nf * 0.29'" 
pd="'2*int((nf+1)/2) * (W/nf + 0.29)'"
as="'int((nf+2)/2) * W/nf * 0.29'" 
ps="'2*int((nf+2)/2) * (W/nf + 0.29)'"
nrd="'0.29 / W'" nrs="'0.29 / W'"
sa=0 sb=0 sd=0
model=nfet_01v8
spiceprefix=X
}
C {sky130_fd_pr/nfet_01v8.sym} 2710 -270 1 0 {name=M57
L=0.15
W=1
nf=1 
mult=1
ad="'int((nf+1)/2) * W/nf * 0.29'" 
pd="'2*int((nf+1)/2) * (W/nf + 0.29)'"
as="'int((nf+2)/2) * W/nf * 0.29'" 
ps="'2*int((nf+2)/2) * (W/nf + 0.29)'"
nrd="'0.29 / W'" nrs="'0.29 / W'"
sa=0 sb=0 sd=0
model=nfet_01v8
spiceprefix=X
}
C {sky130_fd_pr/nfet_01v8.sym} 2510 -420 3 1 {name=M58
L=0.15
W=1
nf=1 
mult=1
ad="'int((nf+1)/2) * W/nf * 0.29'" 
pd="'2*int((nf+1)/2) * (W/nf + 0.29)'"
as="'int((nf+2)/2) * W/nf * 0.29'" 
ps="'2*int((nf+2)/2) * (W/nf + 0.29)'"
nrd="'0.29 / W'" nrs="'0.29 / W'"
sa=0 sb=0 sd=0
model=nfet_01v8
spiceprefix=X
}
C {sky130_fd_pr/nfet_01v8.sym} 2610 -380 1 1 {name=M59
L=0.15
W=1
nf=1 
mult=1
ad="'int((nf+1)/2) * W/nf * 0.29'" 
pd="'2*int((nf+1)/2) * (W/nf + 0.29)'"
as="'int((nf+2)/2) * W/nf * 0.29'" 
ps="'2*int((nf+2)/2) * (W/nf + 0.29)'"
nrd="'0.29 / W'" nrs="'0.29 / W'"
sa=0 sb=0 sd=0
model=nfet_01v8
spiceprefix=X
}
C {sky130_fd_pr/nfet_01v8.sym} 2710 -420 1 0 {name=M60
L=0.15
W=1
nf=1 
mult=1
ad="'int((nf+1)/2) * W/nf * 0.29'" 
pd="'2*int((nf+1)/2) * (W/nf + 0.29)'"
as="'int((nf+2)/2) * W/nf * 0.29'" 
ps="'2*int((nf+2)/2) * (W/nf + 0.29)'"
nrd="'0.29 / W'" nrs="'0.29 / W'"
sa=0 sb=0 sd=0
model=nfet_01v8
spiceprefix=X
}
C {sky130_fd_pr/pfet_01v8.sym} 2180 -690 1 0 {name=M61
L=0.15
W=1
nf=1
mult=1
ad="'int((nf+1)/2) * W/nf * 0.29'" 
pd="'2*int((nf+1)/2) * (W/nf + 0.29)'"
as="'int((nf+2)/2) * W/nf * 0.29'" 
ps="'2*int((nf+2)/2) * (W/nf + 0.29)'"
nrd="'0.29 / W'" nrs="'0.29 / W'"
sa=0 sb=0 sd=0
model=pfet_01v8
spiceprefix=X
}
C {sky130_fd_pr/pfet_01v8.sym} 2280 -650 3 0 {name=M62
L=0.15
W=1
nf=1
mult=1
ad="'int((nf+1)/2) * W/nf * 0.29'" 
pd="'2*int((nf+1)/2) * (W/nf + 0.29)'"
as="'int((nf+2)/2) * W/nf * 0.29'" 
ps="'2*int((nf+2)/2) * (W/nf + 0.29)'"
nrd="'0.29 / W'" nrs="'0.29 / W'"
sa=0 sb=0 sd=0
model=pfet_01v8
spiceprefix=X
}
C {sky130_fd_pr/pfet_01v8.sym} 2380 -650 3 0 {name=M63
L=0.15
W=1
nf=1
mult=1
ad="'int((nf+1)/2) * W/nf * 0.29'" 
pd="'2*int((nf+1)/2) * (W/nf + 0.29)'"
as="'int((nf+2)/2) * W/nf * 0.29'" 
ps="'2*int((nf+2)/2) * (W/nf + 0.29)'"
nrd="'0.29 / W'" nrs="'0.29 / W'"
sa=0 sb=0 sd=0
model=pfet_01v8
spiceprefix=X
}
C {sky130_fd_pr/pfet_01v8.sym} 2380 -520 3 0 {name=M64
L=0.15
W=1
nf=1
mult=1
ad="'int((nf+1)/2) * W/nf * 0.29'" 
pd="'2*int((nf+1)/2) * (W/nf + 0.29)'"
as="'int((nf+2)/2) * W/nf * 0.29'" 
ps="'2*int((nf+2)/2) * (W/nf + 0.29)'"
nrd="'0.29 / W'" nrs="'0.29 / W'"
sa=0 sb=0 sd=0
model=pfet_01v8
spiceprefix=X
}
C {sky130_fd_pr/pfet_01v8.sym} 2280 -520 3 0 {name=M65
L=0.15
W=1
nf=1
mult=1
ad="'int((nf+1)/2) * W/nf * 0.29'" 
pd="'2*int((nf+1)/2) * (W/nf + 0.29)'"
as="'int((nf+2)/2) * W/nf * 0.29'" 
ps="'2*int((nf+2)/2) * (W/nf + 0.29)'"
nrd="'0.29 / W'" nrs="'0.29 / W'"
sa=0 sb=0 sd=0
model=pfet_01v8
spiceprefix=X
}
C {sky130_fd_pr/pfet_01v8.sym} 2180 -520 1 1 {name=M66
L=0.15
W=1
nf=1
mult=1
ad="'int((nf+1)/2) * W/nf * 0.29'" 
pd="'2*int((nf+1)/2) * (W/nf + 0.29)'"
as="'int((nf+2)/2) * W/nf * 0.29'" 
ps="'2*int((nf+2)/2) * (W/nf + 0.29)'"
nrd="'0.29 / W'" nrs="'0.29 / W'"
sa=0 sb=0 sd=0
model=pfet_01v8
spiceprefix=X
}
C {sky130_fd_pr/pfet_01v8.sym} 2510 -520 3 0 {name=M67
L=0.15
W=1
nf=1
mult=1
ad="'int((nf+1)/2) * W/nf * 0.29'" 
pd="'2*int((nf+1)/2) * (W/nf + 0.29)'"
as="'int((nf+2)/2) * W/nf * 0.29'" 
ps="'2*int((nf+2)/2) * (W/nf + 0.29)'"
nrd="'0.29 / W'" nrs="'0.29 / W'"
sa=0 sb=0 sd=0
model=pfet_01v8
spiceprefix=X
}
C {sky130_fd_pr/pfet_01v8.sym} 2510 -690 3 1 {name=M68
L=0.15
W=1
nf=1
mult=1
ad="'int((nf+1)/2) * W/nf * 0.29'" 
pd="'2*int((nf+1)/2) * (W/nf + 0.29)'"
as="'int((nf+2)/2) * W/nf * 0.29'" 
ps="'2*int((nf+2)/2) * (W/nf + 0.29)'"
nrd="'0.29 / W'" nrs="'0.29 / W'"
sa=0 sb=0 sd=0
model=pfet_01v8
spiceprefix=X
}
C {sky130_fd_pr/pfet_01v8.sym} 2610 -520 3 0 {name=M69
L=0.15
W=1
nf=1
mult=1
ad="'int((nf+1)/2) * W/nf * 0.29'" 
pd="'2*int((nf+1)/2) * (W/nf + 0.29)'"
as="'int((nf+2)/2) * W/nf * 0.29'" 
ps="'2*int((nf+2)/2) * (W/nf + 0.29)'"
nrd="'0.29 / W'" nrs="'0.29 / W'"
sa=0 sb=0 sd=0
model=pfet_01v8
spiceprefix=X
}
C {sky130_fd_pr/pfet_01v8.sym} 2710 -520 1 1 {name=M70
L=0.15
W=1
nf=1
mult=1
ad="'int((nf+1)/2) * W/nf * 0.29'" 
pd="'2*int((nf+1)/2) * (W/nf + 0.29)'"
as="'int((nf+2)/2) * W/nf * 0.29'" 
ps="'2*int((nf+2)/2) * (W/nf + 0.29)'"
nrd="'0.29 / W'" nrs="'0.29 / W'"
sa=0 sb=0 sd=0
model=pfet_01v8
spiceprefix=X
}
C {sky130_fd_pr/pfet_01v8.sym} 2710 -650 1 1 {name=M71
L=0.15
W=1
nf=1
mult=1
ad="'int((nf+1)/2) * W/nf * 0.29'" 
pd="'2*int((nf+1)/2) * (W/nf + 0.29)'"
as="'int((nf+2)/2) * W/nf * 0.29'" 
ps="'2*int((nf+2)/2) * (W/nf + 0.29)'"
nrd="'0.29 / W'" nrs="'0.29 / W'"
sa=0 sb=0 sd=0
model=pfet_01v8
spiceprefix=X
}
C {sky130_fd_pr/pfet_01v8.sym} 2610 -650 3 0 {name=M72
L=0.15
W=1
nf=1
mult=1
ad="'int((nf+1)/2) * W/nf * 0.29'" 
pd="'2*int((nf+1)/2) * (W/nf + 0.29)'"
as="'int((nf+2)/2) * W/nf * 0.29'" 
ps="'2*int((nf+2)/2) * (W/nf + 0.29)'"
nrd="'0.29 / W'" nrs="'0.29 / W'"
sa=0 sb=0 sd=0
model=pfet_01v8
spiceprefix=X
}
C {sky130_fd_pr/nfet_01v8.sym} 2900 -230 1 1 {name=M73
L=0.15
W=1
nf=1 
mult=1
ad="'int((nf+1)/2) * W/nf * 0.29'" 
pd="'2*int((nf+1)/2) * (W/nf + 0.29)'"
as="'int((nf+2)/2) * W/nf * 0.29'" 
ps="'2*int((nf+2)/2) * (W/nf + 0.29)'"
nrd="'0.29 / W'" nrs="'0.29 / W'"
sa=0 sb=0 sd=0
model=nfet_01v8
spiceprefix=X
}
C {sky130_fd_pr/nfet_01v8.sym} 3000 -230 1 1 {name=M74
L=0.15
W=1
nf=1 
mult=1
ad="'int((nf+1)/2) * W/nf * 0.29'" 
pd="'2*int((nf+1)/2) * (W/nf + 0.29)'"
as="'int((nf+2)/2) * W/nf * 0.29'" 
ps="'2*int((nf+2)/2) * (W/nf + 0.29)'"
nrd="'0.29 / W'" nrs="'0.29 / W'"
sa=0 sb=0 sd=0
model=nfet_01v8
spiceprefix=X
}
C {sky130_fd_pr/nfet_01v8.sym} 3100 -270 1 0 {name=M75
L=0.15
W=1
nf=1 
mult=1
ad="'int((nf+1)/2) * W/nf * 0.29'" 
pd="'2*int((nf+1)/2) * (W/nf + 0.29)'"
as="'int((nf+2)/2) * W/nf * 0.29'" 
ps="'2*int((nf+2)/2) * (W/nf + 0.29)'"
nrd="'0.29 / W'" nrs="'0.29 / W'"
sa=0 sb=0 sd=0
model=nfet_01v8
spiceprefix=X
}
C {sky130_fd_pr/nfet_01v8.sym} 2900 -420 1 0 {name=M76
L=0.15
W=1
nf=1 
mult=1
ad="'int((nf+1)/2) * W/nf * 0.29'" 
pd="'2*int((nf+1)/2) * (W/nf + 0.29)'"
as="'int((nf+2)/2) * W/nf * 0.29'" 
ps="'2*int((nf+2)/2) * (W/nf + 0.29)'"
nrd="'0.29 / W'" nrs="'0.29 / W'"
sa=0 sb=0 sd=0
model=nfet_01v8
spiceprefix=X
}
C {sky130_fd_pr/nfet_01v8.sym} 3000 -380 3 0 {name=M77
L=0.15
W=1
nf=1 
mult=1
ad="'int((nf+1)/2) * W/nf * 0.29'" 
pd="'2*int((nf+1)/2) * (W/nf + 0.29)'"
as="'int((nf+2)/2) * W/nf * 0.29'" 
ps="'2*int((nf+2)/2) * (W/nf + 0.29)'"
nrd="'0.29 / W'" nrs="'0.29 / W'"
sa=0 sb=0 sd=0
model=nfet_01v8
spiceprefix=X
}
C {sky130_fd_pr/nfet_01v8.sym} 3100 -420 3 1 {name=M78
L=0.15
W=1
nf=1 
mult=1
ad="'int((nf+1)/2) * W/nf * 0.29'" 
pd="'2*int((nf+1)/2) * (W/nf + 0.29)'"
as="'int((nf+2)/2) * W/nf * 0.29'" 
ps="'2*int((nf+2)/2) * (W/nf + 0.29)'"
nrd="'0.29 / W'" nrs="'0.29 / W'"
sa=0 sb=0 sd=0
model=nfet_01v8
spiceprefix=X
}
C {sky130_fd_pr/nfet_01v8.sym} 3230 -230 3 0 {name=M79
L=0.15
W=1
nf=1 
mult=1
ad="'int((nf+1)/2) * W/nf * 0.29'" 
pd="'2*int((nf+1)/2) * (W/nf + 0.29)'"
as="'int((nf+2)/2) * W/nf * 0.29'" 
ps="'2*int((nf+2)/2) * (W/nf + 0.29)'"
nrd="'0.29 / W'" nrs="'0.29 / W'"
sa=0 sb=0 sd=0
model=nfet_01v8
spiceprefix=X
}
C {sky130_fd_pr/nfet_01v8.sym} 3330 -230 1 1 {name=M80
L=0.15
W=1
nf=1 
mult=1
ad="'int((nf+1)/2) * W/nf * 0.29'" 
pd="'2*int((nf+1)/2) * (W/nf + 0.29)'"
as="'int((nf+2)/2) * W/nf * 0.29'" 
ps="'2*int((nf+2)/2) * (W/nf + 0.29)'"
nrd="'0.29 / W'" nrs="'0.29 / W'"
sa=0 sb=0 sd=0
model=nfet_01v8
spiceprefix=X
}
C {sky130_fd_pr/nfet_01v8.sym} 3430 -270 1 0 {name=M81
L=0.15
W=1
nf=1 
mult=1
ad="'int((nf+1)/2) * W/nf * 0.29'" 
pd="'2*int((nf+1)/2) * (W/nf + 0.29)'"
as="'int((nf+2)/2) * W/nf * 0.29'" 
ps="'2*int((nf+2)/2) * (W/nf + 0.29)'"
nrd="'0.29 / W'" nrs="'0.29 / W'"
sa=0 sb=0 sd=0
model=nfet_01v8
spiceprefix=X
}
C {sky130_fd_pr/nfet_01v8.sym} 3230 -420 3 1 {name=M82
L=0.15
W=1
nf=1 
mult=1
ad="'int((nf+1)/2) * W/nf * 0.29'" 
pd="'2*int((nf+1)/2) * (W/nf + 0.29)'"
as="'int((nf+2)/2) * W/nf * 0.29'" 
ps="'2*int((nf+2)/2) * (W/nf + 0.29)'"
nrd="'0.29 / W'" nrs="'0.29 / W'"
sa=0 sb=0 sd=0
model=nfet_01v8
spiceprefix=X
}
C {sky130_fd_pr/nfet_01v8.sym} 3330 -380 1 1 {name=M83
L=0.15
W=1
nf=1 
mult=1
ad="'int((nf+1)/2) * W/nf * 0.29'" 
pd="'2*int((nf+1)/2) * (W/nf + 0.29)'"
as="'int((nf+2)/2) * W/nf * 0.29'" 
ps="'2*int((nf+2)/2) * (W/nf + 0.29)'"
nrd="'0.29 / W'" nrs="'0.29 / W'"
sa=0 sb=0 sd=0
model=nfet_01v8
spiceprefix=X
}
C {sky130_fd_pr/nfet_01v8.sym} 3430 -420 1 0 {name=M84
L=0.15
W=1
nf=1 
mult=1
ad="'int((nf+1)/2) * W/nf * 0.29'" 
pd="'2*int((nf+1)/2) * (W/nf + 0.29)'"
as="'int((nf+2)/2) * W/nf * 0.29'" 
ps="'2*int((nf+2)/2) * (W/nf + 0.29)'"
nrd="'0.29 / W'" nrs="'0.29 / W'"
sa=0 sb=0 sd=0
model=nfet_01v8
spiceprefix=X
}
C {sky130_fd_pr/pfet_01v8.sym} 2900 -690 1 0 {name=M85
L=0.15
W=1
nf=1
mult=1
ad="'int((nf+1)/2) * W/nf * 0.29'" 
pd="'2*int((nf+1)/2) * (W/nf + 0.29)'"
as="'int((nf+2)/2) * W/nf * 0.29'" 
ps="'2*int((nf+2)/2) * (W/nf + 0.29)'"
nrd="'0.29 / W'" nrs="'0.29 / W'"
sa=0 sb=0 sd=0
model=pfet_01v8
spiceprefix=X
}
C {sky130_fd_pr/pfet_01v8.sym} 3000 -650 3 0 {name=M86
L=0.15
W=1
nf=1
mult=1
ad="'int((nf+1)/2) * W/nf * 0.29'" 
pd="'2*int((nf+1)/2) * (W/nf + 0.29)'"
as="'int((nf+2)/2) * W/nf * 0.29'" 
ps="'2*int((nf+2)/2) * (W/nf + 0.29)'"
nrd="'0.29 / W'" nrs="'0.29 / W'"
sa=0 sb=0 sd=0
model=pfet_01v8
spiceprefix=X
}
C {sky130_fd_pr/pfet_01v8.sym} 3100 -650 3 0 {name=M87
L=0.15
W=1
nf=1
mult=1
ad="'int((nf+1)/2) * W/nf * 0.29'" 
pd="'2*int((nf+1)/2) * (W/nf + 0.29)'"
as="'int((nf+2)/2) * W/nf * 0.29'" 
ps="'2*int((nf+2)/2) * (W/nf + 0.29)'"
nrd="'0.29 / W'" nrs="'0.29 / W'"
sa=0 sb=0 sd=0
model=pfet_01v8
spiceprefix=X
}
C {sky130_fd_pr/pfet_01v8.sym} 3100 -520 3 0 {name=M88
L=0.15
W=1
nf=1
mult=1
ad="'int((nf+1)/2) * W/nf * 0.29'" 
pd="'2*int((nf+1)/2) * (W/nf + 0.29)'"
as="'int((nf+2)/2) * W/nf * 0.29'" 
ps="'2*int((nf+2)/2) * (W/nf + 0.29)'"
nrd="'0.29 / W'" nrs="'0.29 / W'"
sa=0 sb=0 sd=0
model=pfet_01v8
spiceprefix=X
}
C {sky130_fd_pr/pfet_01v8.sym} 3000 -520 3 0 {name=M89
L=0.15
W=1
nf=1
mult=1
ad="'int((nf+1)/2) * W/nf * 0.29'" 
pd="'2*int((nf+1)/2) * (W/nf + 0.29)'"
as="'int((nf+2)/2) * W/nf * 0.29'" 
ps="'2*int((nf+2)/2) * (W/nf + 0.29)'"
nrd="'0.29 / W'" nrs="'0.29 / W'"
sa=0 sb=0 sd=0
model=pfet_01v8
spiceprefix=X
}
C {sky130_fd_pr/pfet_01v8.sym} 2900 -520 1 1 {name=M90
L=0.15
W=1
nf=1
mult=1
ad="'int((nf+1)/2) * W/nf * 0.29'" 
pd="'2*int((nf+1)/2) * (W/nf + 0.29)'"
as="'int((nf+2)/2) * W/nf * 0.29'" 
ps="'2*int((nf+2)/2) * (W/nf + 0.29)'"
nrd="'0.29 / W'" nrs="'0.29 / W'"
sa=0 sb=0 sd=0
model=pfet_01v8
spiceprefix=X
}
C {sky130_fd_pr/pfet_01v8.sym} 3230 -520 3 0 {name=M91
L=0.15
W=1
nf=1
mult=1
ad="'int((nf+1)/2) * W/nf * 0.29'" 
pd="'2*int((nf+1)/2) * (W/nf + 0.29)'"
as="'int((nf+2)/2) * W/nf * 0.29'" 
ps="'2*int((nf+2)/2) * (W/nf + 0.29)'"
nrd="'0.29 / W'" nrs="'0.29 / W'"
sa=0 sb=0 sd=0
model=pfet_01v8
spiceprefix=X
}
C {sky130_fd_pr/pfet_01v8.sym} 3230 -690 3 1 {name=M92
L=0.15
W=1
nf=1
mult=1
ad="'int((nf+1)/2) * W/nf * 0.29'" 
pd="'2*int((nf+1)/2) * (W/nf + 0.29)'"
as="'int((nf+2)/2) * W/nf * 0.29'" 
ps="'2*int((nf+2)/2) * (W/nf + 0.29)'"
nrd="'0.29 / W'" nrs="'0.29 / W'"
sa=0 sb=0 sd=0
model=pfet_01v8
spiceprefix=X
}
C {sky130_fd_pr/pfet_01v8.sym} 3330 -520 3 0 {name=M93
L=0.15
W=1
nf=1
mult=1
ad="'int((nf+1)/2) * W/nf * 0.29'" 
pd="'2*int((nf+1)/2) * (W/nf + 0.29)'"
as="'int((nf+2)/2) * W/nf * 0.29'" 
ps="'2*int((nf+2)/2) * (W/nf + 0.29)'"
nrd="'0.29 / W'" nrs="'0.29 / W'"
sa=0 sb=0 sd=0
model=pfet_01v8
spiceprefix=X
}
C {sky130_fd_pr/pfet_01v8.sym} 3430 -520 1 1 {name=M94
L=0.15
W=1
nf=1
mult=1
ad="'int((nf+1)/2) * W/nf * 0.29'" 
pd="'2*int((nf+1)/2) * (W/nf + 0.29)'"
as="'int((nf+2)/2) * W/nf * 0.29'" 
ps="'2*int((nf+2)/2) * (W/nf + 0.29)'"
nrd="'0.29 / W'" nrs="'0.29 / W'"
sa=0 sb=0 sd=0
model=pfet_01v8
spiceprefix=X
}
C {sky130_fd_pr/pfet_01v8.sym} 3430 -650 1 1 {name=M95
L=0.15
W=1
nf=1
mult=1
ad="'int((nf+1)/2) * W/nf * 0.29'" 
pd="'2*int((nf+1)/2) * (W/nf + 0.29)'"
as="'int((nf+2)/2) * W/nf * 0.29'" 
ps="'2*int((nf+2)/2) * (W/nf + 0.29)'"
nrd="'0.29 / W'" nrs="'0.29 / W'"
sa=0 sb=0 sd=0
model=pfet_01v8
spiceprefix=X
}
C {sky130_fd_pr/pfet_01v8.sym} 3330 -650 3 0 {name=M96
L=0.15
W=1
nf=1
mult=1
ad="'int((nf+1)/2) * W/nf * 0.29'" 
pd="'2*int((nf+1)/2) * (W/nf + 0.29)'"
as="'int((nf+2)/2) * W/nf * 0.29'" 
ps="'2*int((nf+2)/2) * (W/nf + 0.29)'"
nrd="'0.29 / W'" nrs="'0.29 / W'"
sa=0 sb=0 sd=0
model=pfet_01v8
spiceprefix=X
}
